VERSION 5.8 ;
BUSBITCHARS "[]" ;
DIVIDERCHAR "/" ;
UNITS
    DATABASE MICRONS 1000 ;
END UNITS

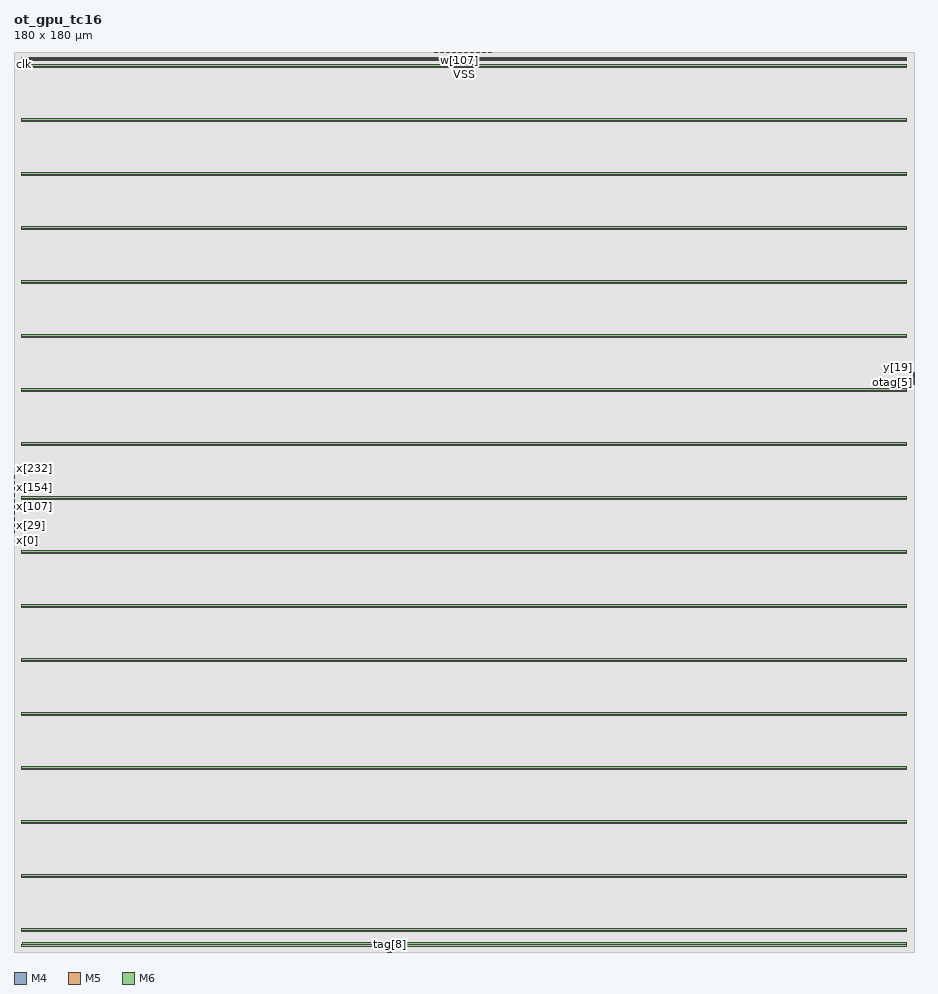
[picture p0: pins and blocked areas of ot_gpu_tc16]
MACRO ot_gpu_tc16
  FOREIGN ot_gpu_tc16 0 0 ;
  CLASS BLOCK ;
  SIZE 180 BY 180 ;
  PIN clk
    DIRECTION INPUT ;
    USE SIGNAL ;
    PORT
      LAYER M4 ;
        RECT  0 177.456 0.084 177.48 ;
    END
  END clk
  PIN fault
    DIRECTION OUTPUT ;
    USE SIGNAL ;
    PORT
      LAYER M4 ;
        RECT  179.916 113.52 180 113.544 ;
    END
  END fault
  PIN first
    DIRECTION INPUT ;
    USE SIGNAL ;
    PORT
      LAYER M5 ;
        RECT  74.64 0 74.664 0.084 ;
    END
  END first
  PIN last
    DIRECTION INPUT ;
    USE SIGNAL ;
    PORT
      LAYER M5 ;
        RECT  74.688 0 74.712 0.084 ;
    END
  END last
  PIN otag[0]
    DIRECTION OUTPUT ;
    USE SIGNAL ;
    PORT
      LAYER M4 ;
        RECT  179.916 113.568 180 113.592 ;
    END
  END otag[0]
  PIN otag[10]
    DIRECTION OUTPUT ;
    USE SIGNAL ;
    PORT
      LAYER M4 ;
        RECT  179.916 114.048 180 114.072 ;
    END
  END otag[10]
  PIN otag[11]
    DIRECTION OUTPUT ;
    USE SIGNAL ;
    PORT
      LAYER M4 ;
        RECT  179.916 114.096 180 114.12 ;
    END
  END otag[11]
  PIN otag[12]
    DIRECTION OUTPUT ;
    USE SIGNAL ;
    PORT
      LAYER M4 ;
        RECT  179.916 114.144 180 114.168 ;
    END
  END otag[12]
  PIN otag[13]
    DIRECTION OUTPUT ;
    USE SIGNAL ;
    PORT
      LAYER M4 ;
        RECT  179.916 114.192 180 114.216 ;
    END
  END otag[13]
  PIN otag[14]
    DIRECTION OUTPUT ;
    USE SIGNAL ;
    PORT
      LAYER M4 ;
        RECT  179.916 114.24 180 114.264 ;
    END
  END otag[14]
  PIN otag[15]
    DIRECTION OUTPUT ;
    USE SIGNAL ;
    PORT
      LAYER M4 ;
        RECT  179.916 114.288 180 114.312 ;
    END
  END otag[15]
  PIN otag[1]
    DIRECTION OUTPUT ;
    USE SIGNAL ;
    PORT
      LAYER M4 ;
        RECT  179.916 113.616 180 113.64 ;
    END
  END otag[1]
  PIN otag[2]
    DIRECTION OUTPUT ;
    USE SIGNAL ;
    PORT
      LAYER M4 ;
        RECT  179.916 113.664 180 113.688 ;
    END
  END otag[2]
  PIN otag[3]
    DIRECTION OUTPUT ;
    USE SIGNAL ;
    PORT
      LAYER M4 ;
        RECT  179.916 113.712 180 113.736 ;
    END
  END otag[3]
  PIN otag[4]
    DIRECTION OUTPUT ;
    USE SIGNAL ;
    PORT
      LAYER M4 ;
        RECT  179.916 113.76 180 113.784 ;
    END
  END otag[4]
  PIN otag[5]
    DIRECTION OUTPUT ;
    USE SIGNAL ;
    PORT
      LAYER M4 ;
        RECT  179.916 113.808 180 113.832 ;
    END
  END otag[5]
  PIN otag[6]
    DIRECTION OUTPUT ;
    USE SIGNAL ;
    PORT
      LAYER M4 ;
        RECT  179.916 113.856 180 113.88 ;
    END
  END otag[6]
  PIN otag[7]
    DIRECTION OUTPUT ;
    USE SIGNAL ;
    PORT
      LAYER M4 ;
        RECT  179.916 113.904 180 113.928 ;
    END
  END otag[7]
  PIN otag[8]
    DIRECTION OUTPUT ;
    USE SIGNAL ;
    PORT
      LAYER M4 ;
        RECT  179.916 113.952 180 113.976 ;
    END
  END otag[8]
  PIN otag[9]
    DIRECTION OUTPUT ;
    USE SIGNAL ;
    PORT
      LAYER M4 ;
        RECT  179.916 114 180 114.024 ;
    END
  END otag[9]
  PIN ov
    DIRECTION OUTPUT ;
    USE SIGNAL ;
    PORT
      LAYER M4 ;
        RECT  179.916 114.336 180 114.36 ;
    END
  END ov
  PIN rst_n
    DIRECTION INPUT ;
    USE SIGNAL ;
    PORT
      LAYER M5 ;
        RECT  74.736 0 74.76 0.084 ;
    END
  END rst_n
  PIN tag[0]
    DIRECTION INPUT ;
    USE SIGNAL ;
    PORT
      LAYER M5 ;
        RECT  74.784 0 74.808 0.084 ;
    END
  END tag[0]
  PIN tag[10]
    DIRECTION INPUT ;
    USE SIGNAL ;
    PORT
      LAYER M5 ;
        RECT  75.264 0 75.288 0.084 ;
    END
  END tag[10]
  PIN tag[11]
    DIRECTION INPUT ;
    USE SIGNAL ;
    PORT
      LAYER M5 ;
        RECT  75.312 0 75.336 0.084 ;
    END
  END tag[11]
  PIN tag[12]
    DIRECTION INPUT ;
    USE SIGNAL ;
    PORT
      LAYER M5 ;
        RECT  75.36 0 75.384 0.084 ;
    END
  END tag[12]
  PIN tag[13]
    DIRECTION INPUT ;
    USE SIGNAL ;
    PORT
      LAYER M5 ;
        RECT  75.408 0 75.432 0.084 ;
    END
  END tag[13]
  PIN tag[14]
    DIRECTION INPUT ;
    USE SIGNAL ;
    PORT
      LAYER M5 ;
        RECT  75.456 0 75.48 0.084 ;
    END
  END tag[14]
  PIN tag[15]
    DIRECTION INPUT ;
    USE SIGNAL ;
    PORT
      LAYER M5 ;
        RECT  75.504 0 75.528 0.084 ;
    END
  END tag[15]
  PIN tag[1]
    DIRECTION INPUT ;
    USE SIGNAL ;
    PORT
      LAYER M5 ;
        RECT  74.832 0 74.856 0.084 ;
    END
  END tag[1]
  PIN tag[2]
    DIRECTION INPUT ;
    USE SIGNAL ;
    PORT
      LAYER M5 ;
        RECT  74.88 0 74.904 0.084 ;
    END
  END tag[2]
  PIN tag[3]
    DIRECTION INPUT ;
    USE SIGNAL ;
    PORT
      LAYER M5 ;
        RECT  74.928 0 74.952 0.084 ;
    END
  END tag[3]
  PIN tag[4]
    DIRECTION INPUT ;
    USE SIGNAL ;
    PORT
      LAYER M5 ;
        RECT  74.976 0 75 0.084 ;
    END
  END tag[4]
  PIN tag[5]
    DIRECTION INPUT ;
    USE SIGNAL ;
    PORT
      LAYER M5 ;
        RECT  75.024 0 75.048 0.084 ;
    END
  END tag[5]
  PIN tag[6]
    DIRECTION INPUT ;
    USE SIGNAL ;
    PORT
      LAYER M5 ;
        RECT  75.072 0 75.096 0.084 ;
    END
  END tag[6]
  PIN tag[7]
    DIRECTION INPUT ;
    USE SIGNAL ;
    PORT
      LAYER M5 ;
        RECT  75.12 0 75.144 0.084 ;
    END
  END tag[7]
  PIN tag[8]
    DIRECTION INPUT ;
    USE SIGNAL ;
    PORT
      LAYER M5 ;
        RECT  75.168 0 75.192 0.084 ;
    END
  END tag[8]
  PIN tag[9]
    DIRECTION INPUT ;
    USE SIGNAL ;
    PORT
      LAYER M5 ;
        RECT  75.216 0 75.24 0.084 ;
    END
  END tag[9]
  PIN v
    DIRECTION INPUT ;
    USE SIGNAL ;
    PORT
      LAYER M5 ;
        RECT  75.552 0 75.576 0.084 ;
    END
  END v
  PIN w[0]
    DIRECTION INPUT ;
    USE SIGNAL ;
    PORT
      LAYER M5 ;
        RECT  83.904 179.916 83.928 180 ;
    END
  END w[0]
  PIN w[100]
    DIRECTION INPUT ;
    USE SIGNAL ;
    PORT
      LAYER M5 ;
        RECT  88.704 179.916 88.728 180 ;
    END
  END w[100]
  PIN w[101]
    DIRECTION INPUT ;
    USE SIGNAL ;
    PORT
      LAYER M5 ;
        RECT  88.752 179.916 88.776 180 ;
    END
  END w[101]
  PIN w[102]
    DIRECTION INPUT ;
    USE SIGNAL ;
    PORT
      LAYER M5 ;
        RECT  88.8 179.916 88.824 180 ;
    END
  END w[102]
  PIN w[103]
    DIRECTION INPUT ;
    USE SIGNAL ;
    PORT
      LAYER M5 ;
        RECT  88.848 179.916 88.872 180 ;
    END
  END w[103]
  PIN w[104]
    DIRECTION INPUT ;
    USE SIGNAL ;
    PORT
      LAYER M5 ;
        RECT  88.896 179.916 88.92 180 ;
    END
  END w[104]
  PIN w[105]
    DIRECTION INPUT ;
    USE SIGNAL ;
    PORT
      LAYER M5 ;
        RECT  88.944 179.916 88.968 180 ;
    END
  END w[105]
  PIN w[106]
    DIRECTION INPUT ;
    USE SIGNAL ;
    PORT
      LAYER M5 ;
        RECT  88.992 179.916 89.016 180 ;
    END
  END w[106]
  PIN w[107]
    DIRECTION INPUT ;
    USE SIGNAL ;
    PORT
      LAYER M5 ;
        RECT  89.04 179.916 89.064 180 ;
    END
  END w[107]
  PIN w[108]
    DIRECTION INPUT ;
    USE SIGNAL ;
    PORT
      LAYER M5 ;
        RECT  89.088 179.916 89.112 180 ;
    END
  END w[108]
  PIN w[109]
    DIRECTION INPUT ;
    USE SIGNAL ;
    PORT
      LAYER M5 ;
        RECT  89.136 179.916 89.16 180 ;
    END
  END w[109]
  PIN w[10]
    DIRECTION INPUT ;
    USE SIGNAL ;
    PORT
      LAYER M5 ;
        RECT  84.384 179.916 84.408 180 ;
    END
  END w[10]
  PIN w[110]
    DIRECTION INPUT ;
    USE SIGNAL ;
    PORT
      LAYER M5 ;
        RECT  89.184 179.916 89.208 180 ;
    END
  END w[110]
  PIN w[111]
    DIRECTION INPUT ;
    USE SIGNAL ;
    PORT
      LAYER M5 ;
        RECT  89.232 179.916 89.256 180 ;
    END
  END w[111]
  PIN w[112]
    DIRECTION INPUT ;
    USE SIGNAL ;
    PORT
      LAYER M5 ;
        RECT  89.28 179.916 89.304 180 ;
    END
  END w[112]
  PIN w[113]
    DIRECTION INPUT ;
    USE SIGNAL ;
    PORT
      LAYER M5 ;
        RECT  89.328 179.916 89.352 180 ;
    END
  END w[113]
  PIN w[114]
    DIRECTION INPUT ;
    USE SIGNAL ;
    PORT
      LAYER M5 ;
        RECT  89.376 179.916 89.4 180 ;
    END
  END w[114]
  PIN w[115]
    DIRECTION INPUT ;
    USE SIGNAL ;
    PORT
      LAYER M5 ;
        RECT  89.424 179.916 89.448 180 ;
    END
  END w[115]
  PIN w[116]
    DIRECTION INPUT ;
    USE SIGNAL ;
    PORT
      LAYER M5 ;
        RECT  89.472 179.916 89.496 180 ;
    END
  END w[116]
  PIN w[117]
    DIRECTION INPUT ;
    USE SIGNAL ;
    PORT
      LAYER M5 ;
        RECT  89.52 179.916 89.544 180 ;
    END
  END w[117]
  PIN w[118]
    DIRECTION INPUT ;
    USE SIGNAL ;
    PORT
      LAYER M5 ;
        RECT  89.568 179.916 89.592 180 ;
    END
  END w[118]
  PIN w[119]
    DIRECTION INPUT ;
    USE SIGNAL ;
    PORT
      LAYER M5 ;
        RECT  89.616 179.916 89.64 180 ;
    END
  END w[119]
  PIN w[11]
    DIRECTION INPUT ;
    USE SIGNAL ;
    PORT
      LAYER M5 ;
        RECT  84.432 179.916 84.456 180 ;
    END
  END w[11]
  PIN w[120]
    DIRECTION INPUT ;
    USE SIGNAL ;
    PORT
      LAYER M5 ;
        RECT  89.664 179.916 89.688 180 ;
    END
  END w[120]
  PIN w[121]
    DIRECTION INPUT ;
    USE SIGNAL ;
    PORT
      LAYER M5 ;
        RECT  89.712 179.916 89.736 180 ;
    END
  END w[121]
  PIN w[122]
    DIRECTION INPUT ;
    USE SIGNAL ;
    PORT
      LAYER M5 ;
        RECT  89.76 179.916 89.784 180 ;
    END
  END w[122]
  PIN w[123]
    DIRECTION INPUT ;
    USE SIGNAL ;
    PORT
      LAYER M5 ;
        RECT  89.808 179.916 89.832 180 ;
    END
  END w[123]
  PIN w[124]
    DIRECTION INPUT ;
    USE SIGNAL ;
    PORT
      LAYER M5 ;
        RECT  89.856 179.916 89.88 180 ;
    END
  END w[124]
  PIN w[125]
    DIRECTION INPUT ;
    USE SIGNAL ;
    PORT
      LAYER M5 ;
        RECT  89.904 179.916 89.928 180 ;
    END
  END w[125]
  PIN w[126]
    DIRECTION INPUT ;
    USE SIGNAL ;
    PORT
      LAYER M5 ;
        RECT  89.952 179.916 89.976 180 ;
    END
  END w[126]
  PIN w[127]
    DIRECTION INPUT ;
    USE SIGNAL ;
    PORT
      LAYER M5 ;
        RECT  90 179.916 90.024 180 ;
    END
  END w[127]
  PIN w[128]
    DIRECTION INPUT ;
    USE SIGNAL ;
    PORT
      LAYER M5 ;
        RECT  90.048 179.916 90.072 180 ;
    END
  END w[128]
  PIN w[129]
    DIRECTION INPUT ;
    USE SIGNAL ;
    PORT
      LAYER M5 ;
        RECT  90.096 179.916 90.12 180 ;
    END
  END w[129]
  PIN w[12]
    DIRECTION INPUT ;
    USE SIGNAL ;
    PORT
      LAYER M5 ;
        RECT  84.48 179.916 84.504 180 ;
    END
  END w[12]
  PIN w[130]
    DIRECTION INPUT ;
    USE SIGNAL ;
    PORT
      LAYER M5 ;
        RECT  90.144 179.916 90.168 180 ;
    END
  END w[130]
  PIN w[131]
    DIRECTION INPUT ;
    USE SIGNAL ;
    PORT
      LAYER M5 ;
        RECT  90.192 179.916 90.216 180 ;
    END
  END w[131]
  PIN w[132]
    DIRECTION INPUT ;
    USE SIGNAL ;
    PORT
      LAYER M5 ;
        RECT  90.24 179.916 90.264 180 ;
    END
  END w[132]
  PIN w[133]
    DIRECTION INPUT ;
    USE SIGNAL ;
    PORT
      LAYER M5 ;
        RECT  90.288 179.916 90.312 180 ;
    END
  END w[133]
  PIN w[134]
    DIRECTION INPUT ;
    USE SIGNAL ;
    PORT
      LAYER M5 ;
        RECT  90.336 179.916 90.36 180 ;
    END
  END w[134]
  PIN w[135]
    DIRECTION INPUT ;
    USE SIGNAL ;
    PORT
      LAYER M5 ;
        RECT  90.384 179.916 90.408 180 ;
    END
  END w[135]
  PIN w[136]
    DIRECTION INPUT ;
    USE SIGNAL ;
    PORT
      LAYER M5 ;
        RECT  90.432 179.916 90.456 180 ;
    END
  END w[136]
  PIN w[137]
    DIRECTION INPUT ;
    USE SIGNAL ;
    PORT
      LAYER M5 ;
        RECT  90.48 179.916 90.504 180 ;
    END
  END w[137]
  PIN w[138]
    DIRECTION INPUT ;
    USE SIGNAL ;
    PORT
      LAYER M5 ;
        RECT  90.528 179.916 90.552 180 ;
    END
  END w[138]
  PIN w[139]
    DIRECTION INPUT ;
    USE SIGNAL ;
    PORT
      LAYER M5 ;
        RECT  90.576 179.916 90.6 180 ;
    END
  END w[139]
  PIN w[13]
    DIRECTION INPUT ;
    USE SIGNAL ;
    PORT
      LAYER M5 ;
        RECT  84.528 179.916 84.552 180 ;
    END
  END w[13]
  PIN w[140]
    DIRECTION INPUT ;
    USE SIGNAL ;
    PORT
      LAYER M5 ;
        RECT  90.624 179.916 90.648 180 ;
    END
  END w[140]
  PIN w[141]
    DIRECTION INPUT ;
    USE SIGNAL ;
    PORT
      LAYER M5 ;
        RECT  90.672 179.916 90.696 180 ;
    END
  END w[141]
  PIN w[142]
    DIRECTION INPUT ;
    USE SIGNAL ;
    PORT
      LAYER M5 ;
        RECT  90.72 179.916 90.744 180 ;
    END
  END w[142]
  PIN w[143]
    DIRECTION INPUT ;
    USE SIGNAL ;
    PORT
      LAYER M5 ;
        RECT  90.768 179.916 90.792 180 ;
    END
  END w[143]
  PIN w[144]
    DIRECTION INPUT ;
    USE SIGNAL ;
    PORT
      LAYER M5 ;
        RECT  90.816 179.916 90.84 180 ;
    END
  END w[144]
  PIN w[145]
    DIRECTION INPUT ;
    USE SIGNAL ;
    PORT
      LAYER M5 ;
        RECT  90.864 179.916 90.888 180 ;
    END
  END w[145]
  PIN w[146]
    DIRECTION INPUT ;
    USE SIGNAL ;
    PORT
      LAYER M5 ;
        RECT  90.912 179.916 90.936 180 ;
    END
  END w[146]
  PIN w[147]
    DIRECTION INPUT ;
    USE SIGNAL ;
    PORT
      LAYER M5 ;
        RECT  90.96 179.916 90.984 180 ;
    END
  END w[147]
  PIN w[148]
    DIRECTION INPUT ;
    USE SIGNAL ;
    PORT
      LAYER M5 ;
        RECT  91.008 179.916 91.032 180 ;
    END
  END w[148]
  PIN w[149]
    DIRECTION INPUT ;
    USE SIGNAL ;
    PORT
      LAYER M5 ;
        RECT  91.056 179.916 91.08 180 ;
    END
  END w[149]
  PIN w[14]
    DIRECTION INPUT ;
    USE SIGNAL ;
    PORT
      LAYER M5 ;
        RECT  84.576 179.916 84.6 180 ;
    END
  END w[14]
  PIN w[150]
    DIRECTION INPUT ;
    USE SIGNAL ;
    PORT
      LAYER M5 ;
        RECT  91.104 179.916 91.128 180 ;
    END
  END w[150]
  PIN w[151]
    DIRECTION INPUT ;
    USE SIGNAL ;
    PORT
      LAYER M5 ;
        RECT  91.152 179.916 91.176 180 ;
    END
  END w[151]
  PIN w[152]
    DIRECTION INPUT ;
    USE SIGNAL ;
    PORT
      LAYER M5 ;
        RECT  91.2 179.916 91.224 180 ;
    END
  END w[152]
  PIN w[153]
    DIRECTION INPUT ;
    USE SIGNAL ;
    PORT
      LAYER M5 ;
        RECT  91.248 179.916 91.272 180 ;
    END
  END w[153]
  PIN w[154]
    DIRECTION INPUT ;
    USE SIGNAL ;
    PORT
      LAYER M5 ;
        RECT  91.296 179.916 91.32 180 ;
    END
  END w[154]
  PIN w[155]
    DIRECTION INPUT ;
    USE SIGNAL ;
    PORT
      LAYER M5 ;
        RECT  91.344 179.916 91.368 180 ;
    END
  END w[155]
  PIN w[156]
    DIRECTION INPUT ;
    USE SIGNAL ;
    PORT
      LAYER M5 ;
        RECT  91.392 179.916 91.416 180 ;
    END
  END w[156]
  PIN w[157]
    DIRECTION INPUT ;
    USE SIGNAL ;
    PORT
      LAYER M5 ;
        RECT  91.44 179.916 91.464 180 ;
    END
  END w[157]
  PIN w[158]
    DIRECTION INPUT ;
    USE SIGNAL ;
    PORT
      LAYER M5 ;
        RECT  91.488 179.916 91.512 180 ;
    END
  END w[158]
  PIN w[159]
    DIRECTION INPUT ;
    USE SIGNAL ;
    PORT
      LAYER M5 ;
        RECT  91.536 179.916 91.56 180 ;
    END
  END w[159]
  PIN w[15]
    DIRECTION INPUT ;
    USE SIGNAL ;
    PORT
      LAYER M5 ;
        RECT  84.624 179.916 84.648 180 ;
    END
  END w[15]
  PIN w[160]
    DIRECTION INPUT ;
    USE SIGNAL ;
    PORT
      LAYER M5 ;
        RECT  91.584 179.916 91.608 180 ;
    END
  END w[160]
  PIN w[161]
    DIRECTION INPUT ;
    USE SIGNAL ;
    PORT
      LAYER M5 ;
        RECT  91.632 179.916 91.656 180 ;
    END
  END w[161]
  PIN w[162]
    DIRECTION INPUT ;
    USE SIGNAL ;
    PORT
      LAYER M5 ;
        RECT  91.68 179.916 91.704 180 ;
    END
  END w[162]
  PIN w[163]
    DIRECTION INPUT ;
    USE SIGNAL ;
    PORT
      LAYER M5 ;
        RECT  91.728 179.916 91.752 180 ;
    END
  END w[163]
  PIN w[164]
    DIRECTION INPUT ;
    USE SIGNAL ;
    PORT
      LAYER M5 ;
        RECT  91.776 179.916 91.8 180 ;
    END
  END w[164]
  PIN w[165]
    DIRECTION INPUT ;
    USE SIGNAL ;
    PORT
      LAYER M5 ;
        RECT  91.824 179.916 91.848 180 ;
    END
  END w[165]
  PIN w[166]
    DIRECTION INPUT ;
    USE SIGNAL ;
    PORT
      LAYER M5 ;
        RECT  91.872 179.916 91.896 180 ;
    END
  END w[166]
  PIN w[167]
    DIRECTION INPUT ;
    USE SIGNAL ;
    PORT
      LAYER M5 ;
        RECT  91.92 179.916 91.944 180 ;
    END
  END w[167]
  PIN w[168]
    DIRECTION INPUT ;
    USE SIGNAL ;
    PORT
      LAYER M5 ;
        RECT  91.968 179.916 91.992 180 ;
    END
  END w[168]
  PIN w[169]
    DIRECTION INPUT ;
    USE SIGNAL ;
    PORT
      LAYER M5 ;
        RECT  92.016 179.916 92.04 180 ;
    END
  END w[169]
  PIN w[16]
    DIRECTION INPUT ;
    USE SIGNAL ;
    PORT
      LAYER M5 ;
        RECT  84.672 179.916 84.696 180 ;
    END
  END w[16]
  PIN w[170]
    DIRECTION INPUT ;
    USE SIGNAL ;
    PORT
      LAYER M5 ;
        RECT  92.064 179.916 92.088 180 ;
    END
  END w[170]
  PIN w[171]
    DIRECTION INPUT ;
    USE SIGNAL ;
    PORT
      LAYER M5 ;
        RECT  92.112 179.916 92.136 180 ;
    END
  END w[171]
  PIN w[172]
    DIRECTION INPUT ;
    USE SIGNAL ;
    PORT
      LAYER M5 ;
        RECT  92.16 179.916 92.184 180 ;
    END
  END w[172]
  PIN w[173]
    DIRECTION INPUT ;
    USE SIGNAL ;
    PORT
      LAYER M5 ;
        RECT  92.208 179.916 92.232 180 ;
    END
  END w[173]
  PIN w[174]
    DIRECTION INPUT ;
    USE SIGNAL ;
    PORT
      LAYER M5 ;
        RECT  92.256 179.916 92.28 180 ;
    END
  END w[174]
  PIN w[175]
    DIRECTION INPUT ;
    USE SIGNAL ;
    PORT
      LAYER M5 ;
        RECT  92.304 179.916 92.328 180 ;
    END
  END w[175]
  PIN w[176]
    DIRECTION INPUT ;
    USE SIGNAL ;
    PORT
      LAYER M5 ;
        RECT  92.352 179.916 92.376 180 ;
    END
  END w[176]
  PIN w[177]
    DIRECTION INPUT ;
    USE SIGNAL ;
    PORT
      LAYER M5 ;
        RECT  92.4 179.916 92.424 180 ;
    END
  END w[177]
  PIN w[178]
    DIRECTION INPUT ;
    USE SIGNAL ;
    PORT
      LAYER M5 ;
        RECT  92.448 179.916 92.472 180 ;
    END
  END w[178]
  PIN w[179]
    DIRECTION INPUT ;
    USE SIGNAL ;
    PORT
      LAYER M5 ;
        RECT  92.496 179.916 92.52 180 ;
    END
  END w[179]
  PIN w[17]
    DIRECTION INPUT ;
    USE SIGNAL ;
    PORT
      LAYER M5 ;
        RECT  84.72 179.916 84.744 180 ;
    END
  END w[17]
  PIN w[180]
    DIRECTION INPUT ;
    USE SIGNAL ;
    PORT
      LAYER M5 ;
        RECT  92.544 179.916 92.568 180 ;
    END
  END w[180]
  PIN w[181]
    DIRECTION INPUT ;
    USE SIGNAL ;
    PORT
      LAYER M5 ;
        RECT  92.592 179.916 92.616 180 ;
    END
  END w[181]
  PIN w[182]
    DIRECTION INPUT ;
    USE SIGNAL ;
    PORT
      LAYER M5 ;
        RECT  92.64 179.916 92.664 180 ;
    END
  END w[182]
  PIN w[183]
    DIRECTION INPUT ;
    USE SIGNAL ;
    PORT
      LAYER M5 ;
        RECT  92.688 179.916 92.712 180 ;
    END
  END w[183]
  PIN w[184]
    DIRECTION INPUT ;
    USE SIGNAL ;
    PORT
      LAYER M5 ;
        RECT  92.736 179.916 92.76 180 ;
    END
  END w[184]
  PIN w[185]
    DIRECTION INPUT ;
    USE SIGNAL ;
    PORT
      LAYER M5 ;
        RECT  92.784 179.916 92.808 180 ;
    END
  END w[185]
  PIN w[186]
    DIRECTION INPUT ;
    USE SIGNAL ;
    PORT
      LAYER M5 ;
        RECT  92.832 179.916 92.856 180 ;
    END
  END w[186]
  PIN w[187]
    DIRECTION INPUT ;
    USE SIGNAL ;
    PORT
      LAYER M5 ;
        RECT  92.88 179.916 92.904 180 ;
    END
  END w[187]
  PIN w[188]
    DIRECTION INPUT ;
    USE SIGNAL ;
    PORT
      LAYER M5 ;
        RECT  92.928 179.916 92.952 180 ;
    END
  END w[188]
  PIN w[189]
    DIRECTION INPUT ;
    USE SIGNAL ;
    PORT
      LAYER M5 ;
        RECT  92.976 179.916 93 180 ;
    END
  END w[189]
  PIN w[18]
    DIRECTION INPUT ;
    USE SIGNAL ;
    PORT
      LAYER M5 ;
        RECT  84.768 179.916 84.792 180 ;
    END
  END w[18]
  PIN w[190]
    DIRECTION INPUT ;
    USE SIGNAL ;
    PORT
      LAYER M5 ;
        RECT  93.024 179.916 93.048 180 ;
    END
  END w[190]
  PIN w[191]
    DIRECTION INPUT ;
    USE SIGNAL ;
    PORT
      LAYER M5 ;
        RECT  93.072 179.916 93.096 180 ;
    END
  END w[191]
  PIN w[192]
    DIRECTION INPUT ;
    USE SIGNAL ;
    PORT
      LAYER M5 ;
        RECT  93.12 179.916 93.144 180 ;
    END
  END w[192]
  PIN w[193]
    DIRECTION INPUT ;
    USE SIGNAL ;
    PORT
      LAYER M5 ;
        RECT  93.168 179.916 93.192 180 ;
    END
  END w[193]
  PIN w[194]
    DIRECTION INPUT ;
    USE SIGNAL ;
    PORT
      LAYER M5 ;
        RECT  93.216 179.916 93.24 180 ;
    END
  END w[194]
  PIN w[195]
    DIRECTION INPUT ;
    USE SIGNAL ;
    PORT
      LAYER M5 ;
        RECT  93.264 179.916 93.288 180 ;
    END
  END w[195]
  PIN w[196]
    DIRECTION INPUT ;
    USE SIGNAL ;
    PORT
      LAYER M5 ;
        RECT  93.312 179.916 93.336 180 ;
    END
  END w[196]
  PIN w[197]
    DIRECTION INPUT ;
    USE SIGNAL ;
    PORT
      LAYER M5 ;
        RECT  93.36 179.916 93.384 180 ;
    END
  END w[197]
  PIN w[198]
    DIRECTION INPUT ;
    USE SIGNAL ;
    PORT
      LAYER M5 ;
        RECT  93.408 179.916 93.432 180 ;
    END
  END w[198]
  PIN w[199]
    DIRECTION INPUT ;
    USE SIGNAL ;
    PORT
      LAYER M5 ;
        RECT  93.456 179.916 93.48 180 ;
    END
  END w[199]
  PIN w[19]
    DIRECTION INPUT ;
    USE SIGNAL ;
    PORT
      LAYER M5 ;
        RECT  84.816 179.916 84.84 180 ;
    END
  END w[19]
  PIN w[1]
    DIRECTION INPUT ;
    USE SIGNAL ;
    PORT
      LAYER M5 ;
        RECT  83.952 179.916 83.976 180 ;
    END
  END w[1]
  PIN w[200]
    DIRECTION INPUT ;
    USE SIGNAL ;
    PORT
      LAYER M5 ;
        RECT  93.504 179.916 93.528 180 ;
    END
  END w[200]
  PIN w[201]
    DIRECTION INPUT ;
    USE SIGNAL ;
    PORT
      LAYER M5 ;
        RECT  93.552 179.916 93.576 180 ;
    END
  END w[201]
  PIN w[202]
    DIRECTION INPUT ;
    USE SIGNAL ;
    PORT
      LAYER M5 ;
        RECT  93.6 179.916 93.624 180 ;
    END
  END w[202]
  PIN w[203]
    DIRECTION INPUT ;
    USE SIGNAL ;
    PORT
      LAYER M5 ;
        RECT  93.648 179.916 93.672 180 ;
    END
  END w[203]
  PIN w[204]
    DIRECTION INPUT ;
    USE SIGNAL ;
    PORT
      LAYER M5 ;
        RECT  93.696 179.916 93.72 180 ;
    END
  END w[204]
  PIN w[205]
    DIRECTION INPUT ;
    USE SIGNAL ;
    PORT
      LAYER M5 ;
        RECT  93.744 179.916 93.768 180 ;
    END
  END w[205]
  PIN w[206]
    DIRECTION INPUT ;
    USE SIGNAL ;
    PORT
      LAYER M5 ;
        RECT  93.792 179.916 93.816 180 ;
    END
  END w[206]
  PIN w[207]
    DIRECTION INPUT ;
    USE SIGNAL ;
    PORT
      LAYER M5 ;
        RECT  93.84 179.916 93.864 180 ;
    END
  END w[207]
  PIN w[208]
    DIRECTION INPUT ;
    USE SIGNAL ;
    PORT
      LAYER M5 ;
        RECT  93.888 179.916 93.912 180 ;
    END
  END w[208]
  PIN w[209]
    DIRECTION INPUT ;
    USE SIGNAL ;
    PORT
      LAYER M5 ;
        RECT  93.936 179.916 93.96 180 ;
    END
  END w[209]
  PIN w[20]
    DIRECTION INPUT ;
    USE SIGNAL ;
    PORT
      LAYER M5 ;
        RECT  84.864 179.916 84.888 180 ;
    END
  END w[20]
  PIN w[210]
    DIRECTION INPUT ;
    USE SIGNAL ;
    PORT
      LAYER M5 ;
        RECT  93.984 179.916 94.008 180 ;
    END
  END w[210]
  PIN w[211]
    DIRECTION INPUT ;
    USE SIGNAL ;
    PORT
      LAYER M5 ;
        RECT  94.032 179.916 94.056 180 ;
    END
  END w[211]
  PIN w[212]
    DIRECTION INPUT ;
    USE SIGNAL ;
    PORT
      LAYER M5 ;
        RECT  94.08 179.916 94.104 180 ;
    END
  END w[212]
  PIN w[213]
    DIRECTION INPUT ;
    USE SIGNAL ;
    PORT
      LAYER M5 ;
        RECT  94.128 179.916 94.152 180 ;
    END
  END w[213]
  PIN w[214]
    DIRECTION INPUT ;
    USE SIGNAL ;
    PORT
      LAYER M5 ;
        RECT  94.176 179.916 94.2 180 ;
    END
  END w[214]
  PIN w[215]
    DIRECTION INPUT ;
    USE SIGNAL ;
    PORT
      LAYER M5 ;
        RECT  94.224 179.916 94.248 180 ;
    END
  END w[215]
  PIN w[216]
    DIRECTION INPUT ;
    USE SIGNAL ;
    PORT
      LAYER M5 ;
        RECT  94.272 179.916 94.296 180 ;
    END
  END w[216]
  PIN w[217]
    DIRECTION INPUT ;
    USE SIGNAL ;
    PORT
      LAYER M5 ;
        RECT  94.32 179.916 94.344 180 ;
    END
  END w[217]
  PIN w[218]
    DIRECTION INPUT ;
    USE SIGNAL ;
    PORT
      LAYER M5 ;
        RECT  94.368 179.916 94.392 180 ;
    END
  END w[218]
  PIN w[219]
    DIRECTION INPUT ;
    USE SIGNAL ;
    PORT
      LAYER M5 ;
        RECT  94.416 179.916 94.44 180 ;
    END
  END w[219]
  PIN w[21]
    DIRECTION INPUT ;
    USE SIGNAL ;
    PORT
      LAYER M5 ;
        RECT  84.912 179.916 84.936 180 ;
    END
  END w[21]
  PIN w[220]
    DIRECTION INPUT ;
    USE SIGNAL ;
    PORT
      LAYER M5 ;
        RECT  94.464 179.916 94.488 180 ;
    END
  END w[220]
  PIN w[221]
    DIRECTION INPUT ;
    USE SIGNAL ;
    PORT
      LAYER M5 ;
        RECT  94.512 179.916 94.536 180 ;
    END
  END w[221]
  PIN w[222]
    DIRECTION INPUT ;
    USE SIGNAL ;
    PORT
      LAYER M5 ;
        RECT  94.56 179.916 94.584 180 ;
    END
  END w[222]
  PIN w[223]
    DIRECTION INPUT ;
    USE SIGNAL ;
    PORT
      LAYER M5 ;
        RECT  94.608 179.916 94.632 180 ;
    END
  END w[223]
  PIN w[224]
    DIRECTION INPUT ;
    USE SIGNAL ;
    PORT
      LAYER M5 ;
        RECT  94.656 179.916 94.68 180 ;
    END
  END w[224]
  PIN w[225]
    DIRECTION INPUT ;
    USE SIGNAL ;
    PORT
      LAYER M5 ;
        RECT  94.704 179.916 94.728 180 ;
    END
  END w[225]
  PIN w[226]
    DIRECTION INPUT ;
    USE SIGNAL ;
    PORT
      LAYER M5 ;
        RECT  94.752 179.916 94.776 180 ;
    END
  END w[226]
  PIN w[227]
    DIRECTION INPUT ;
    USE SIGNAL ;
    PORT
      LAYER M5 ;
        RECT  94.8 179.916 94.824 180 ;
    END
  END w[227]
  PIN w[228]
    DIRECTION INPUT ;
    USE SIGNAL ;
    PORT
      LAYER M5 ;
        RECT  94.848 179.916 94.872 180 ;
    END
  END w[228]
  PIN w[229]
    DIRECTION INPUT ;
    USE SIGNAL ;
    PORT
      LAYER M5 ;
        RECT  94.896 179.916 94.92 180 ;
    END
  END w[229]
  PIN w[22]
    DIRECTION INPUT ;
    USE SIGNAL ;
    PORT
      LAYER M5 ;
        RECT  84.96 179.916 84.984 180 ;
    END
  END w[22]
  PIN w[230]
    DIRECTION INPUT ;
    USE SIGNAL ;
    PORT
      LAYER M5 ;
        RECT  94.944 179.916 94.968 180 ;
    END
  END w[230]
  PIN w[231]
    DIRECTION INPUT ;
    USE SIGNAL ;
    PORT
      LAYER M5 ;
        RECT  94.992 179.916 95.016 180 ;
    END
  END w[231]
  PIN w[232]
    DIRECTION INPUT ;
    USE SIGNAL ;
    PORT
      LAYER M5 ;
        RECT  95.04 179.916 95.064 180 ;
    END
  END w[232]
  PIN w[233]
    DIRECTION INPUT ;
    USE SIGNAL ;
    PORT
      LAYER M5 ;
        RECT  95.088 179.916 95.112 180 ;
    END
  END w[233]
  PIN w[234]
    DIRECTION INPUT ;
    USE SIGNAL ;
    PORT
      LAYER M5 ;
        RECT  95.136 179.916 95.16 180 ;
    END
  END w[234]
  PIN w[235]
    DIRECTION INPUT ;
    USE SIGNAL ;
    PORT
      LAYER M5 ;
        RECT  95.184 179.916 95.208 180 ;
    END
  END w[235]
  PIN w[236]
    DIRECTION INPUT ;
    USE SIGNAL ;
    PORT
      LAYER M5 ;
        RECT  95.232 179.916 95.256 180 ;
    END
  END w[236]
  PIN w[237]
    DIRECTION INPUT ;
    USE SIGNAL ;
    PORT
      LAYER M5 ;
        RECT  95.28 179.916 95.304 180 ;
    END
  END w[237]
  PIN w[238]
    DIRECTION INPUT ;
    USE SIGNAL ;
    PORT
      LAYER M5 ;
        RECT  95.328 179.916 95.352 180 ;
    END
  END w[238]
  PIN w[239]
    DIRECTION INPUT ;
    USE SIGNAL ;
    PORT
      LAYER M5 ;
        RECT  95.376 179.916 95.4 180 ;
    END
  END w[239]
  PIN w[23]
    DIRECTION INPUT ;
    USE SIGNAL ;
    PORT
      LAYER M5 ;
        RECT  85.008 179.916 85.032 180 ;
    END
  END w[23]
  PIN w[240]
    DIRECTION INPUT ;
    USE SIGNAL ;
    PORT
      LAYER M5 ;
        RECT  95.424 179.916 95.448 180 ;
    END
  END w[240]
  PIN w[241]
    DIRECTION INPUT ;
    USE SIGNAL ;
    PORT
      LAYER M5 ;
        RECT  95.472 179.916 95.496 180 ;
    END
  END w[241]
  PIN w[242]
    DIRECTION INPUT ;
    USE SIGNAL ;
    PORT
      LAYER M5 ;
        RECT  95.52 179.916 95.544 180 ;
    END
  END w[242]
  PIN w[243]
    DIRECTION INPUT ;
    USE SIGNAL ;
    PORT
      LAYER M5 ;
        RECT  95.568 179.916 95.592 180 ;
    END
  END w[243]
  PIN w[244]
    DIRECTION INPUT ;
    USE SIGNAL ;
    PORT
      LAYER M5 ;
        RECT  95.616 179.916 95.64 180 ;
    END
  END w[244]
  PIN w[245]
    DIRECTION INPUT ;
    USE SIGNAL ;
    PORT
      LAYER M5 ;
        RECT  95.664 179.916 95.688 180 ;
    END
  END w[245]
  PIN w[246]
    DIRECTION INPUT ;
    USE SIGNAL ;
    PORT
      LAYER M5 ;
        RECT  95.712 179.916 95.736 180 ;
    END
  END w[246]
  PIN w[247]
    DIRECTION INPUT ;
    USE SIGNAL ;
    PORT
      LAYER M5 ;
        RECT  95.76 179.916 95.784 180 ;
    END
  END w[247]
  PIN w[248]
    DIRECTION INPUT ;
    USE SIGNAL ;
    PORT
      LAYER M5 ;
        RECT  95.808 179.916 95.832 180 ;
    END
  END w[248]
  PIN w[249]
    DIRECTION INPUT ;
    USE SIGNAL ;
    PORT
      LAYER M5 ;
        RECT  95.856 179.916 95.88 180 ;
    END
  END w[249]
  PIN w[24]
    DIRECTION INPUT ;
    USE SIGNAL ;
    PORT
      LAYER M5 ;
        RECT  85.056 179.916 85.08 180 ;
    END
  END w[24]
  PIN w[250]
    DIRECTION INPUT ;
    USE SIGNAL ;
    PORT
      LAYER M5 ;
        RECT  95.904 179.916 95.928 180 ;
    END
  END w[250]
  PIN w[251]
    DIRECTION INPUT ;
    USE SIGNAL ;
    PORT
      LAYER M5 ;
        RECT  95.952 179.916 95.976 180 ;
    END
  END w[251]
  PIN w[252]
    DIRECTION INPUT ;
    USE SIGNAL ;
    PORT
      LAYER M5 ;
        RECT  96 179.916 96.024 180 ;
    END
  END w[252]
  PIN w[253]
    DIRECTION INPUT ;
    USE SIGNAL ;
    PORT
      LAYER M5 ;
        RECT  96.048 179.916 96.072 180 ;
    END
  END w[253]
  PIN w[254]
    DIRECTION INPUT ;
    USE SIGNAL ;
    PORT
      LAYER M5 ;
        RECT  96.096 179.916 96.12 180 ;
    END
  END w[254]
  PIN w[255]
    DIRECTION INPUT ;
    USE SIGNAL ;
    PORT
      LAYER M5 ;
        RECT  96.144 179.916 96.168 180 ;
    END
  END w[255]
  PIN w[25]
    DIRECTION INPUT ;
    USE SIGNAL ;
    PORT
      LAYER M5 ;
        RECT  85.104 179.916 85.128 180 ;
    END
  END w[25]
  PIN w[26]
    DIRECTION INPUT ;
    USE SIGNAL ;
    PORT
      LAYER M5 ;
        RECT  85.152 179.916 85.176 180 ;
    END
  END w[26]
  PIN w[27]
    DIRECTION INPUT ;
    USE SIGNAL ;
    PORT
      LAYER M5 ;
        RECT  85.2 179.916 85.224 180 ;
    END
  END w[27]
  PIN w[28]
    DIRECTION INPUT ;
    USE SIGNAL ;
    PORT
      LAYER M5 ;
        RECT  85.248 179.916 85.272 180 ;
    END
  END w[28]
  PIN w[29]
    DIRECTION INPUT ;
    USE SIGNAL ;
    PORT
      LAYER M5 ;
        RECT  85.296 179.916 85.32 180 ;
    END
  END w[29]
  PIN w[2]
    DIRECTION INPUT ;
    USE SIGNAL ;
    PORT
      LAYER M5 ;
        RECT  84 179.916 84.024 180 ;
    END
  END w[2]
  PIN w[30]
    DIRECTION INPUT ;
    USE SIGNAL ;
    PORT
      LAYER M5 ;
        RECT  85.344 179.916 85.368 180 ;
    END
  END w[30]
  PIN w[31]
    DIRECTION INPUT ;
    USE SIGNAL ;
    PORT
      LAYER M5 ;
        RECT  85.392 179.916 85.416 180 ;
    END
  END w[31]
  PIN w[32]
    DIRECTION INPUT ;
    USE SIGNAL ;
    PORT
      LAYER M5 ;
        RECT  85.44 179.916 85.464 180 ;
    END
  END w[32]
  PIN w[33]
    DIRECTION INPUT ;
    USE SIGNAL ;
    PORT
      LAYER M5 ;
        RECT  85.488 179.916 85.512 180 ;
    END
  END w[33]
  PIN w[34]
    DIRECTION INPUT ;
    USE SIGNAL ;
    PORT
      LAYER M5 ;
        RECT  85.536 179.916 85.56 180 ;
    END
  END w[34]
  PIN w[35]
    DIRECTION INPUT ;
    USE SIGNAL ;
    PORT
      LAYER M5 ;
        RECT  85.584 179.916 85.608 180 ;
    END
  END w[35]
  PIN w[36]
    DIRECTION INPUT ;
    USE SIGNAL ;
    PORT
      LAYER M5 ;
        RECT  85.632 179.916 85.656 180 ;
    END
  END w[36]
  PIN w[37]
    DIRECTION INPUT ;
    USE SIGNAL ;
    PORT
      LAYER M5 ;
        RECT  85.68 179.916 85.704 180 ;
    END
  END w[37]
  PIN w[38]
    DIRECTION INPUT ;
    USE SIGNAL ;
    PORT
      LAYER M5 ;
        RECT  85.728 179.916 85.752 180 ;
    END
  END w[38]
  PIN w[39]
    DIRECTION INPUT ;
    USE SIGNAL ;
    PORT
      LAYER M5 ;
        RECT  85.776 179.916 85.8 180 ;
    END
  END w[39]
  PIN w[3]
    DIRECTION INPUT ;
    USE SIGNAL ;
    PORT
      LAYER M5 ;
        RECT  84.048 179.916 84.072 180 ;
    END
  END w[3]
  PIN w[40]
    DIRECTION INPUT ;
    USE SIGNAL ;
    PORT
      LAYER M5 ;
        RECT  85.824 179.916 85.848 180 ;
    END
  END w[40]
  PIN w[41]
    DIRECTION INPUT ;
    USE SIGNAL ;
    PORT
      LAYER M5 ;
        RECT  85.872 179.916 85.896 180 ;
    END
  END w[41]
  PIN w[42]
    DIRECTION INPUT ;
    USE SIGNAL ;
    PORT
      LAYER M5 ;
        RECT  85.92 179.916 85.944 180 ;
    END
  END w[42]
  PIN w[43]
    DIRECTION INPUT ;
    USE SIGNAL ;
    PORT
      LAYER M5 ;
        RECT  85.968 179.916 85.992 180 ;
    END
  END w[43]
  PIN w[44]
    DIRECTION INPUT ;
    USE SIGNAL ;
    PORT
      LAYER M5 ;
        RECT  86.016 179.916 86.04 180 ;
    END
  END w[44]
  PIN w[45]
    DIRECTION INPUT ;
    USE SIGNAL ;
    PORT
      LAYER M5 ;
        RECT  86.064 179.916 86.088 180 ;
    END
  END w[45]
  PIN w[46]
    DIRECTION INPUT ;
    USE SIGNAL ;
    PORT
      LAYER M5 ;
        RECT  86.112 179.916 86.136 180 ;
    END
  END w[46]
  PIN w[47]
    DIRECTION INPUT ;
    USE SIGNAL ;
    PORT
      LAYER M5 ;
        RECT  86.16 179.916 86.184 180 ;
    END
  END w[47]
  PIN w[48]
    DIRECTION INPUT ;
    USE SIGNAL ;
    PORT
      LAYER M5 ;
        RECT  86.208 179.916 86.232 180 ;
    END
  END w[48]
  PIN w[49]
    DIRECTION INPUT ;
    USE SIGNAL ;
    PORT
      LAYER M5 ;
        RECT  86.256 179.916 86.28 180 ;
    END
  END w[49]
  PIN w[4]
    DIRECTION INPUT ;
    USE SIGNAL ;
    PORT
      LAYER M5 ;
        RECT  84.096 179.916 84.12 180 ;
    END
  END w[4]
  PIN w[50]
    DIRECTION INPUT ;
    USE SIGNAL ;
    PORT
      LAYER M5 ;
        RECT  86.304 179.916 86.328 180 ;
    END
  END w[50]
  PIN w[51]
    DIRECTION INPUT ;
    USE SIGNAL ;
    PORT
      LAYER M5 ;
        RECT  86.352 179.916 86.376 180 ;
    END
  END w[51]
  PIN w[52]
    DIRECTION INPUT ;
    USE SIGNAL ;
    PORT
      LAYER M5 ;
        RECT  86.4 179.916 86.424 180 ;
    END
  END w[52]
  PIN w[53]
    DIRECTION INPUT ;
    USE SIGNAL ;
    PORT
      LAYER M5 ;
        RECT  86.448 179.916 86.472 180 ;
    END
  END w[53]
  PIN w[54]
    DIRECTION INPUT ;
    USE SIGNAL ;
    PORT
      LAYER M5 ;
        RECT  86.496 179.916 86.52 180 ;
    END
  END w[54]
  PIN w[55]
    DIRECTION INPUT ;
    USE SIGNAL ;
    PORT
      LAYER M5 ;
        RECT  86.544 179.916 86.568 180 ;
    END
  END w[55]
  PIN w[56]
    DIRECTION INPUT ;
    USE SIGNAL ;
    PORT
      LAYER M5 ;
        RECT  86.592 179.916 86.616 180 ;
    END
  END w[56]
  PIN w[57]
    DIRECTION INPUT ;
    USE SIGNAL ;
    PORT
      LAYER M5 ;
        RECT  86.64 179.916 86.664 180 ;
    END
  END w[57]
  PIN w[58]
    DIRECTION INPUT ;
    USE SIGNAL ;
    PORT
      LAYER M5 ;
        RECT  86.688 179.916 86.712 180 ;
    END
  END w[58]
  PIN w[59]
    DIRECTION INPUT ;
    USE SIGNAL ;
    PORT
      LAYER M5 ;
        RECT  86.736 179.916 86.76 180 ;
    END
  END w[59]
  PIN w[5]
    DIRECTION INPUT ;
    USE SIGNAL ;
    PORT
      LAYER M5 ;
        RECT  84.144 179.916 84.168 180 ;
    END
  END w[5]
  PIN w[60]
    DIRECTION INPUT ;
    USE SIGNAL ;
    PORT
      LAYER M5 ;
        RECT  86.784 179.916 86.808 180 ;
    END
  END w[60]
  PIN w[61]
    DIRECTION INPUT ;
    USE SIGNAL ;
    PORT
      LAYER M5 ;
        RECT  86.832 179.916 86.856 180 ;
    END
  END w[61]
  PIN w[62]
    DIRECTION INPUT ;
    USE SIGNAL ;
    PORT
      LAYER M5 ;
        RECT  86.88 179.916 86.904 180 ;
    END
  END w[62]
  PIN w[63]
    DIRECTION INPUT ;
    USE SIGNAL ;
    PORT
      LAYER M5 ;
        RECT  86.928 179.916 86.952 180 ;
    END
  END w[63]
  PIN w[64]
    DIRECTION INPUT ;
    USE SIGNAL ;
    PORT
      LAYER M5 ;
        RECT  86.976 179.916 87 180 ;
    END
  END w[64]
  PIN w[65]
    DIRECTION INPUT ;
    USE SIGNAL ;
    PORT
      LAYER M5 ;
        RECT  87.024 179.916 87.048 180 ;
    END
  END w[65]
  PIN w[66]
    DIRECTION INPUT ;
    USE SIGNAL ;
    PORT
      LAYER M5 ;
        RECT  87.072 179.916 87.096 180 ;
    END
  END w[66]
  PIN w[67]
    DIRECTION INPUT ;
    USE SIGNAL ;
    PORT
      LAYER M5 ;
        RECT  87.12 179.916 87.144 180 ;
    END
  END w[67]
  PIN w[68]
    DIRECTION INPUT ;
    USE SIGNAL ;
    PORT
      LAYER M5 ;
        RECT  87.168 179.916 87.192 180 ;
    END
  END w[68]
  PIN w[69]
    DIRECTION INPUT ;
    USE SIGNAL ;
    PORT
      LAYER M5 ;
        RECT  87.216 179.916 87.24 180 ;
    END
  END w[69]
  PIN w[6]
    DIRECTION INPUT ;
    USE SIGNAL ;
    PORT
      LAYER M5 ;
        RECT  84.192 179.916 84.216 180 ;
    END
  END w[6]
  PIN w[70]
    DIRECTION INPUT ;
    USE SIGNAL ;
    PORT
      LAYER M5 ;
        RECT  87.264 179.916 87.288 180 ;
    END
  END w[70]
  PIN w[71]
    DIRECTION INPUT ;
    USE SIGNAL ;
    PORT
      LAYER M5 ;
        RECT  87.312 179.916 87.336 180 ;
    END
  END w[71]
  PIN w[72]
    DIRECTION INPUT ;
    USE SIGNAL ;
    PORT
      LAYER M5 ;
        RECT  87.36 179.916 87.384 180 ;
    END
  END w[72]
  PIN w[73]
    DIRECTION INPUT ;
    USE SIGNAL ;
    PORT
      LAYER M5 ;
        RECT  87.408 179.916 87.432 180 ;
    END
  END w[73]
  PIN w[74]
    DIRECTION INPUT ;
    USE SIGNAL ;
    PORT
      LAYER M5 ;
        RECT  87.456 179.916 87.48 180 ;
    END
  END w[74]
  PIN w[75]
    DIRECTION INPUT ;
    USE SIGNAL ;
    PORT
      LAYER M5 ;
        RECT  87.504 179.916 87.528 180 ;
    END
  END w[75]
  PIN w[76]
    DIRECTION INPUT ;
    USE SIGNAL ;
    PORT
      LAYER M5 ;
        RECT  87.552 179.916 87.576 180 ;
    END
  END w[76]
  PIN w[77]
    DIRECTION INPUT ;
    USE SIGNAL ;
    PORT
      LAYER M5 ;
        RECT  87.6 179.916 87.624 180 ;
    END
  END w[77]
  PIN w[78]
    DIRECTION INPUT ;
    USE SIGNAL ;
    PORT
      LAYER M5 ;
        RECT  87.648 179.916 87.672 180 ;
    END
  END w[78]
  PIN w[79]
    DIRECTION INPUT ;
    USE SIGNAL ;
    PORT
      LAYER M5 ;
        RECT  87.696 179.916 87.72 180 ;
    END
  END w[79]
  PIN w[7]
    DIRECTION INPUT ;
    USE SIGNAL ;
    PORT
      LAYER M5 ;
        RECT  84.24 179.916 84.264 180 ;
    END
  END w[7]
  PIN w[80]
    DIRECTION INPUT ;
    USE SIGNAL ;
    PORT
      LAYER M5 ;
        RECT  87.744 179.916 87.768 180 ;
    END
  END w[80]
  PIN w[81]
    DIRECTION INPUT ;
    USE SIGNAL ;
    PORT
      LAYER M5 ;
        RECT  87.792 179.916 87.816 180 ;
    END
  END w[81]
  PIN w[82]
    DIRECTION INPUT ;
    USE SIGNAL ;
    PORT
      LAYER M5 ;
        RECT  87.84 179.916 87.864 180 ;
    END
  END w[82]
  PIN w[83]
    DIRECTION INPUT ;
    USE SIGNAL ;
    PORT
      LAYER M5 ;
        RECT  87.888 179.916 87.912 180 ;
    END
  END w[83]
  PIN w[84]
    DIRECTION INPUT ;
    USE SIGNAL ;
    PORT
      LAYER M5 ;
        RECT  87.936 179.916 87.96 180 ;
    END
  END w[84]
  PIN w[85]
    DIRECTION INPUT ;
    USE SIGNAL ;
    PORT
      LAYER M5 ;
        RECT  87.984 179.916 88.008 180 ;
    END
  END w[85]
  PIN w[86]
    DIRECTION INPUT ;
    USE SIGNAL ;
    PORT
      LAYER M5 ;
        RECT  88.032 179.916 88.056 180 ;
    END
  END w[86]
  PIN w[87]
    DIRECTION INPUT ;
    USE SIGNAL ;
    PORT
      LAYER M5 ;
        RECT  88.08 179.916 88.104 180 ;
    END
  END w[87]
  PIN w[88]
    DIRECTION INPUT ;
    USE SIGNAL ;
    PORT
      LAYER M5 ;
        RECT  88.128 179.916 88.152 180 ;
    END
  END w[88]
  PIN w[89]
    DIRECTION INPUT ;
    USE SIGNAL ;
    PORT
      LAYER M5 ;
        RECT  88.176 179.916 88.2 180 ;
    END
  END w[89]
  PIN w[8]
    DIRECTION INPUT ;
    USE SIGNAL ;
    PORT
      LAYER M5 ;
        RECT  84.288 179.916 84.312 180 ;
    END
  END w[8]
  PIN w[90]
    DIRECTION INPUT ;
    USE SIGNAL ;
    PORT
      LAYER M5 ;
        RECT  88.224 179.916 88.248 180 ;
    END
  END w[90]
  PIN w[91]
    DIRECTION INPUT ;
    USE SIGNAL ;
    PORT
      LAYER M5 ;
        RECT  88.272 179.916 88.296 180 ;
    END
  END w[91]
  PIN w[92]
    DIRECTION INPUT ;
    USE SIGNAL ;
    PORT
      LAYER M5 ;
        RECT  88.32 179.916 88.344 180 ;
    END
  END w[92]
  PIN w[93]
    DIRECTION INPUT ;
    USE SIGNAL ;
    PORT
      LAYER M5 ;
        RECT  88.368 179.916 88.392 180 ;
    END
  END w[93]
  PIN w[94]
    DIRECTION INPUT ;
    USE SIGNAL ;
    PORT
      LAYER M5 ;
        RECT  88.416 179.916 88.44 180 ;
    END
  END w[94]
  PIN w[95]
    DIRECTION INPUT ;
    USE SIGNAL ;
    PORT
      LAYER M5 ;
        RECT  88.464 179.916 88.488 180 ;
    END
  END w[95]
  PIN w[96]
    DIRECTION INPUT ;
    USE SIGNAL ;
    PORT
      LAYER M5 ;
        RECT  88.512 179.916 88.536 180 ;
    END
  END w[96]
  PIN w[97]
    DIRECTION INPUT ;
    USE SIGNAL ;
    PORT
      LAYER M5 ;
        RECT  88.56 179.916 88.584 180 ;
    END
  END w[97]
  PIN w[98]
    DIRECTION INPUT ;
    USE SIGNAL ;
    PORT
      LAYER M5 ;
        RECT  88.608 179.916 88.632 180 ;
    END
  END w[98]
  PIN w[99]
    DIRECTION INPUT ;
    USE SIGNAL ;
    PORT
      LAYER M5 ;
        RECT  88.656 179.916 88.68 180 ;
    END
  END w[99]
  PIN w[9]
    DIRECTION INPUT ;
    USE SIGNAL ;
    PORT
      LAYER M5 ;
        RECT  84.336 179.916 84.36 180 ;
    END
  END w[9]
  PIN x[0]
    DIRECTION INPUT ;
    USE SIGNAL ;
    PORT
      LAYER M4 ;
        RECT  0 83.904 0.084 83.928 ;
    END
  END x[0]
  PIN x[100]
    DIRECTION INPUT ;
    USE SIGNAL ;
    PORT
      LAYER M4 ;
        RECT  0 88.704 0.084 88.728 ;
    END
  END x[100]
  PIN x[101]
    DIRECTION INPUT ;
    USE SIGNAL ;
    PORT
      LAYER M4 ;
        RECT  0 88.752 0.084 88.776 ;
    END
  END x[101]
  PIN x[102]
    DIRECTION INPUT ;
    USE SIGNAL ;
    PORT
      LAYER M4 ;
        RECT  0 88.8 0.084 88.824 ;
    END
  END x[102]
  PIN x[103]
    DIRECTION INPUT ;
    USE SIGNAL ;
    PORT
      LAYER M4 ;
        RECT  0 88.848 0.084 88.872 ;
    END
  END x[103]
  PIN x[104]
    DIRECTION INPUT ;
    USE SIGNAL ;
    PORT
      LAYER M4 ;
        RECT  0 88.896 0.084 88.92 ;
    END
  END x[104]
  PIN x[105]
    DIRECTION INPUT ;
    USE SIGNAL ;
    PORT
      LAYER M4 ;
        RECT  0 88.944 0.084 88.968 ;
    END
  END x[105]
  PIN x[106]
    DIRECTION INPUT ;
    USE SIGNAL ;
    PORT
      LAYER M4 ;
        RECT  0 88.992 0.084 89.016 ;
    END
  END x[106]
  PIN x[107]
    DIRECTION INPUT ;
    USE SIGNAL ;
    PORT
      LAYER M4 ;
        RECT  0 89.04 0.084 89.064 ;
    END
  END x[107]
  PIN x[108]
    DIRECTION INPUT ;
    USE SIGNAL ;
    PORT
      LAYER M4 ;
        RECT  0 89.088 0.084 89.112 ;
    END
  END x[108]
  PIN x[109]
    DIRECTION INPUT ;
    USE SIGNAL ;
    PORT
      LAYER M4 ;
        RECT  0 89.136 0.084 89.16 ;
    END
  END x[109]
  PIN x[10]
    DIRECTION INPUT ;
    USE SIGNAL ;
    PORT
      LAYER M4 ;
        RECT  0 84.384 0.084 84.408 ;
    END
  END x[10]
  PIN x[110]
    DIRECTION INPUT ;
    USE SIGNAL ;
    PORT
      LAYER M4 ;
        RECT  0 89.184 0.084 89.208 ;
    END
  END x[110]
  PIN x[111]
    DIRECTION INPUT ;
    USE SIGNAL ;
    PORT
      LAYER M4 ;
        RECT  0 89.232 0.084 89.256 ;
    END
  END x[111]
  PIN x[112]
    DIRECTION INPUT ;
    USE SIGNAL ;
    PORT
      LAYER M4 ;
        RECT  0 89.28 0.084 89.304 ;
    END
  END x[112]
  PIN x[113]
    DIRECTION INPUT ;
    USE SIGNAL ;
    PORT
      LAYER M4 ;
        RECT  0 89.328 0.084 89.352 ;
    END
  END x[113]
  PIN x[114]
    DIRECTION INPUT ;
    USE SIGNAL ;
    PORT
      LAYER M4 ;
        RECT  0 89.376 0.084 89.4 ;
    END
  END x[114]
  PIN x[115]
    DIRECTION INPUT ;
    USE SIGNAL ;
    PORT
      LAYER M4 ;
        RECT  0 89.424 0.084 89.448 ;
    END
  END x[115]
  PIN x[116]
    DIRECTION INPUT ;
    USE SIGNAL ;
    PORT
      LAYER M4 ;
        RECT  0 89.472 0.084 89.496 ;
    END
  END x[116]
  PIN x[117]
    DIRECTION INPUT ;
    USE SIGNAL ;
    PORT
      LAYER M4 ;
        RECT  0 89.52 0.084 89.544 ;
    END
  END x[117]
  PIN x[118]
    DIRECTION INPUT ;
    USE SIGNAL ;
    PORT
      LAYER M4 ;
        RECT  0 89.568 0.084 89.592 ;
    END
  END x[118]
  PIN x[119]
    DIRECTION INPUT ;
    USE SIGNAL ;
    PORT
      LAYER M4 ;
        RECT  0 89.616 0.084 89.64 ;
    END
  END x[119]
  PIN x[11]
    DIRECTION INPUT ;
    USE SIGNAL ;
    PORT
      LAYER M4 ;
        RECT  0 84.432 0.084 84.456 ;
    END
  END x[11]
  PIN x[120]
    DIRECTION INPUT ;
    USE SIGNAL ;
    PORT
      LAYER M4 ;
        RECT  0 89.664 0.084 89.688 ;
    END
  END x[120]
  PIN x[121]
    DIRECTION INPUT ;
    USE SIGNAL ;
    PORT
      LAYER M4 ;
        RECT  0 89.712 0.084 89.736 ;
    END
  END x[121]
  PIN x[122]
    DIRECTION INPUT ;
    USE SIGNAL ;
    PORT
      LAYER M4 ;
        RECT  0 89.76 0.084 89.784 ;
    END
  END x[122]
  PIN x[123]
    DIRECTION INPUT ;
    USE SIGNAL ;
    PORT
      LAYER M4 ;
        RECT  0 89.808 0.084 89.832 ;
    END
  END x[123]
  PIN x[124]
    DIRECTION INPUT ;
    USE SIGNAL ;
    PORT
      LAYER M4 ;
        RECT  0 89.856 0.084 89.88 ;
    END
  END x[124]
  PIN x[125]
    DIRECTION INPUT ;
    USE SIGNAL ;
    PORT
      LAYER M4 ;
        RECT  0 89.904 0.084 89.928 ;
    END
  END x[125]
  PIN x[126]
    DIRECTION INPUT ;
    USE SIGNAL ;
    PORT
      LAYER M4 ;
        RECT  0 89.952 0.084 89.976 ;
    END
  END x[126]
  PIN x[127]
    DIRECTION INPUT ;
    USE SIGNAL ;
    PORT
      LAYER M4 ;
        RECT  0 90 0.084 90.024 ;
    END
  END x[127]
  PIN x[128]
    DIRECTION INPUT ;
    USE SIGNAL ;
    PORT
      LAYER M4 ;
        RECT  0 90.048 0.084 90.072 ;
    END
  END x[128]
  PIN x[129]
    DIRECTION INPUT ;
    USE SIGNAL ;
    PORT
      LAYER M4 ;
        RECT  0 90.096 0.084 90.12 ;
    END
  END x[129]
  PIN x[12]
    DIRECTION INPUT ;
    USE SIGNAL ;
    PORT
      LAYER M4 ;
        RECT  0 84.48 0.084 84.504 ;
    END
  END x[12]
  PIN x[130]
    DIRECTION INPUT ;
    USE SIGNAL ;
    PORT
      LAYER M4 ;
        RECT  0 90.144 0.084 90.168 ;
    END
  END x[130]
  PIN x[131]
    DIRECTION INPUT ;
    USE SIGNAL ;
    PORT
      LAYER M4 ;
        RECT  0 90.192 0.084 90.216 ;
    END
  END x[131]
  PIN x[132]
    DIRECTION INPUT ;
    USE SIGNAL ;
    PORT
      LAYER M4 ;
        RECT  0 90.24 0.084 90.264 ;
    END
  END x[132]
  PIN x[133]
    DIRECTION INPUT ;
    USE SIGNAL ;
    PORT
      LAYER M4 ;
        RECT  0 90.288 0.084 90.312 ;
    END
  END x[133]
  PIN x[134]
    DIRECTION INPUT ;
    USE SIGNAL ;
    PORT
      LAYER M4 ;
        RECT  0 90.336 0.084 90.36 ;
    END
  END x[134]
  PIN x[135]
    DIRECTION INPUT ;
    USE SIGNAL ;
    PORT
      LAYER M4 ;
        RECT  0 90.384 0.084 90.408 ;
    END
  END x[135]
  PIN x[136]
    DIRECTION INPUT ;
    USE SIGNAL ;
    PORT
      LAYER M4 ;
        RECT  0 90.432 0.084 90.456 ;
    END
  END x[136]
  PIN x[137]
    DIRECTION INPUT ;
    USE SIGNAL ;
    PORT
      LAYER M4 ;
        RECT  0 90.48 0.084 90.504 ;
    END
  END x[137]
  PIN x[138]
    DIRECTION INPUT ;
    USE SIGNAL ;
    PORT
      LAYER M4 ;
        RECT  0 90.528 0.084 90.552 ;
    END
  END x[138]
  PIN x[139]
    DIRECTION INPUT ;
    USE SIGNAL ;
    PORT
      LAYER M4 ;
        RECT  0 90.576 0.084 90.6 ;
    END
  END x[139]
  PIN x[13]
    DIRECTION INPUT ;
    USE SIGNAL ;
    PORT
      LAYER M4 ;
        RECT  0 84.528 0.084 84.552 ;
    END
  END x[13]
  PIN x[140]
    DIRECTION INPUT ;
    USE SIGNAL ;
    PORT
      LAYER M4 ;
        RECT  0 90.624 0.084 90.648 ;
    END
  END x[140]
  PIN x[141]
    DIRECTION INPUT ;
    USE SIGNAL ;
    PORT
      LAYER M4 ;
        RECT  0 90.672 0.084 90.696 ;
    END
  END x[141]
  PIN x[142]
    DIRECTION INPUT ;
    USE SIGNAL ;
    PORT
      LAYER M4 ;
        RECT  0 90.72 0.084 90.744 ;
    END
  END x[142]
  PIN x[143]
    DIRECTION INPUT ;
    USE SIGNAL ;
    PORT
      LAYER M4 ;
        RECT  0 90.768 0.084 90.792 ;
    END
  END x[143]
  PIN x[144]
    DIRECTION INPUT ;
    USE SIGNAL ;
    PORT
      LAYER M4 ;
        RECT  0 90.816 0.084 90.84 ;
    END
  END x[144]
  PIN x[145]
    DIRECTION INPUT ;
    USE SIGNAL ;
    PORT
      LAYER M4 ;
        RECT  0 90.864 0.084 90.888 ;
    END
  END x[145]
  PIN x[146]
    DIRECTION INPUT ;
    USE SIGNAL ;
    PORT
      LAYER M4 ;
        RECT  0 90.912 0.084 90.936 ;
    END
  END x[146]
  PIN x[147]
    DIRECTION INPUT ;
    USE SIGNAL ;
    PORT
      LAYER M4 ;
        RECT  0 90.96 0.084 90.984 ;
    END
  END x[147]
  PIN x[148]
    DIRECTION INPUT ;
    USE SIGNAL ;
    PORT
      LAYER M4 ;
        RECT  0 91.008 0.084 91.032 ;
    END
  END x[148]
  PIN x[149]
    DIRECTION INPUT ;
    USE SIGNAL ;
    PORT
      LAYER M4 ;
        RECT  0 91.056 0.084 91.08 ;
    END
  END x[149]
  PIN x[14]
    DIRECTION INPUT ;
    USE SIGNAL ;
    PORT
      LAYER M4 ;
        RECT  0 84.576 0.084 84.6 ;
    END
  END x[14]
  PIN x[150]
    DIRECTION INPUT ;
    USE SIGNAL ;
    PORT
      LAYER M4 ;
        RECT  0 91.104 0.084 91.128 ;
    END
  END x[150]
  PIN x[151]
    DIRECTION INPUT ;
    USE SIGNAL ;
    PORT
      LAYER M4 ;
        RECT  0 91.152 0.084 91.176 ;
    END
  END x[151]
  PIN x[152]
    DIRECTION INPUT ;
    USE SIGNAL ;
    PORT
      LAYER M4 ;
        RECT  0 91.2 0.084 91.224 ;
    END
  END x[152]
  PIN x[153]
    DIRECTION INPUT ;
    USE SIGNAL ;
    PORT
      LAYER M4 ;
        RECT  0 91.248 0.084 91.272 ;
    END
  END x[153]
  PIN x[154]
    DIRECTION INPUT ;
    USE SIGNAL ;
    PORT
      LAYER M4 ;
        RECT  0 91.296 0.084 91.32 ;
    END
  END x[154]
  PIN x[155]
    DIRECTION INPUT ;
    USE SIGNAL ;
    PORT
      LAYER M4 ;
        RECT  0 91.344 0.084 91.368 ;
    END
  END x[155]
  PIN x[156]
    DIRECTION INPUT ;
    USE SIGNAL ;
    PORT
      LAYER M4 ;
        RECT  0 91.392 0.084 91.416 ;
    END
  END x[156]
  PIN x[157]
    DIRECTION INPUT ;
    USE SIGNAL ;
    PORT
      LAYER M4 ;
        RECT  0 91.44 0.084 91.464 ;
    END
  END x[157]
  PIN x[158]
    DIRECTION INPUT ;
    USE SIGNAL ;
    PORT
      LAYER M4 ;
        RECT  0 91.488 0.084 91.512 ;
    END
  END x[158]
  PIN x[159]
    DIRECTION INPUT ;
    USE SIGNAL ;
    PORT
      LAYER M4 ;
        RECT  0 91.536 0.084 91.56 ;
    END
  END x[159]
  PIN x[15]
    DIRECTION INPUT ;
    USE SIGNAL ;
    PORT
      LAYER M4 ;
        RECT  0 84.624 0.084 84.648 ;
    END
  END x[15]
  PIN x[160]
    DIRECTION INPUT ;
    USE SIGNAL ;
    PORT
      LAYER M4 ;
        RECT  0 91.584 0.084 91.608 ;
    END
  END x[160]
  PIN x[161]
    DIRECTION INPUT ;
    USE SIGNAL ;
    PORT
      LAYER M4 ;
        RECT  0 91.632 0.084 91.656 ;
    END
  END x[161]
  PIN x[162]
    DIRECTION INPUT ;
    USE SIGNAL ;
    PORT
      LAYER M4 ;
        RECT  0 91.68 0.084 91.704 ;
    END
  END x[162]
  PIN x[163]
    DIRECTION INPUT ;
    USE SIGNAL ;
    PORT
      LAYER M4 ;
        RECT  0 91.728 0.084 91.752 ;
    END
  END x[163]
  PIN x[164]
    DIRECTION INPUT ;
    USE SIGNAL ;
    PORT
      LAYER M4 ;
        RECT  0 91.776 0.084 91.8 ;
    END
  END x[164]
  PIN x[165]
    DIRECTION INPUT ;
    USE SIGNAL ;
    PORT
      LAYER M4 ;
        RECT  0 91.824 0.084 91.848 ;
    END
  END x[165]
  PIN x[166]
    DIRECTION INPUT ;
    USE SIGNAL ;
    PORT
      LAYER M4 ;
        RECT  0 91.872 0.084 91.896 ;
    END
  END x[166]
  PIN x[167]
    DIRECTION INPUT ;
    USE SIGNAL ;
    PORT
      LAYER M4 ;
        RECT  0 91.92 0.084 91.944 ;
    END
  END x[167]
  PIN x[168]
    DIRECTION INPUT ;
    USE SIGNAL ;
    PORT
      LAYER M4 ;
        RECT  0 91.968 0.084 91.992 ;
    END
  END x[168]
  PIN x[169]
    DIRECTION INPUT ;
    USE SIGNAL ;
    PORT
      LAYER M4 ;
        RECT  0 92.016 0.084 92.04 ;
    END
  END x[169]
  PIN x[16]
    DIRECTION INPUT ;
    USE SIGNAL ;
    PORT
      LAYER M4 ;
        RECT  0 84.672 0.084 84.696 ;
    END
  END x[16]
  PIN x[170]
    DIRECTION INPUT ;
    USE SIGNAL ;
    PORT
      LAYER M4 ;
        RECT  0 92.064 0.084 92.088 ;
    END
  END x[170]
  PIN x[171]
    DIRECTION INPUT ;
    USE SIGNAL ;
    PORT
      LAYER M4 ;
        RECT  0 92.112 0.084 92.136 ;
    END
  END x[171]
  PIN x[172]
    DIRECTION INPUT ;
    USE SIGNAL ;
    PORT
      LAYER M4 ;
        RECT  0 92.16 0.084 92.184 ;
    END
  END x[172]
  PIN x[173]
    DIRECTION INPUT ;
    USE SIGNAL ;
    PORT
      LAYER M4 ;
        RECT  0 92.208 0.084 92.232 ;
    END
  END x[173]
  PIN x[174]
    DIRECTION INPUT ;
    USE SIGNAL ;
    PORT
      LAYER M4 ;
        RECT  0 92.256 0.084 92.28 ;
    END
  END x[174]
  PIN x[175]
    DIRECTION INPUT ;
    USE SIGNAL ;
    PORT
      LAYER M4 ;
        RECT  0 92.304 0.084 92.328 ;
    END
  END x[175]
  PIN x[176]
    DIRECTION INPUT ;
    USE SIGNAL ;
    PORT
      LAYER M4 ;
        RECT  0 92.352 0.084 92.376 ;
    END
  END x[176]
  PIN x[177]
    DIRECTION INPUT ;
    USE SIGNAL ;
    PORT
      LAYER M4 ;
        RECT  0 92.4 0.084 92.424 ;
    END
  END x[177]
  PIN x[178]
    DIRECTION INPUT ;
    USE SIGNAL ;
    PORT
      LAYER M4 ;
        RECT  0 92.448 0.084 92.472 ;
    END
  END x[178]
  PIN x[179]
    DIRECTION INPUT ;
    USE SIGNAL ;
    PORT
      LAYER M4 ;
        RECT  0 92.496 0.084 92.52 ;
    END
  END x[179]
  PIN x[17]
    DIRECTION INPUT ;
    USE SIGNAL ;
    PORT
      LAYER M4 ;
        RECT  0 84.72 0.084 84.744 ;
    END
  END x[17]
  PIN x[180]
    DIRECTION INPUT ;
    USE SIGNAL ;
    PORT
      LAYER M4 ;
        RECT  0 92.544 0.084 92.568 ;
    END
  END x[180]
  PIN x[181]
    DIRECTION INPUT ;
    USE SIGNAL ;
    PORT
      LAYER M4 ;
        RECT  0 92.592 0.084 92.616 ;
    END
  END x[181]
  PIN x[182]
    DIRECTION INPUT ;
    USE SIGNAL ;
    PORT
      LAYER M4 ;
        RECT  0 92.64 0.084 92.664 ;
    END
  END x[182]
  PIN x[183]
    DIRECTION INPUT ;
    USE SIGNAL ;
    PORT
      LAYER M4 ;
        RECT  0 92.688 0.084 92.712 ;
    END
  END x[183]
  PIN x[184]
    DIRECTION INPUT ;
    USE SIGNAL ;
    PORT
      LAYER M4 ;
        RECT  0 92.736 0.084 92.76 ;
    END
  END x[184]
  PIN x[185]
    DIRECTION INPUT ;
    USE SIGNAL ;
    PORT
      LAYER M4 ;
        RECT  0 92.784 0.084 92.808 ;
    END
  END x[185]
  PIN x[186]
    DIRECTION INPUT ;
    USE SIGNAL ;
    PORT
      LAYER M4 ;
        RECT  0 92.832 0.084 92.856 ;
    END
  END x[186]
  PIN x[187]
    DIRECTION INPUT ;
    USE SIGNAL ;
    PORT
      LAYER M4 ;
        RECT  0 92.88 0.084 92.904 ;
    END
  END x[187]
  PIN x[188]
    DIRECTION INPUT ;
    USE SIGNAL ;
    PORT
      LAYER M4 ;
        RECT  0 92.928 0.084 92.952 ;
    END
  END x[188]
  PIN x[189]
    DIRECTION INPUT ;
    USE SIGNAL ;
    PORT
      LAYER M4 ;
        RECT  0 92.976 0.084 93 ;
    END
  END x[189]
  PIN x[18]
    DIRECTION INPUT ;
    USE SIGNAL ;
    PORT
      LAYER M4 ;
        RECT  0 84.768 0.084 84.792 ;
    END
  END x[18]
  PIN x[190]
    DIRECTION INPUT ;
    USE SIGNAL ;
    PORT
      LAYER M4 ;
        RECT  0 93.024 0.084 93.048 ;
    END
  END x[190]
  PIN x[191]
    DIRECTION INPUT ;
    USE SIGNAL ;
    PORT
      LAYER M4 ;
        RECT  0 93.072 0.084 93.096 ;
    END
  END x[191]
  PIN x[192]
    DIRECTION INPUT ;
    USE SIGNAL ;
    PORT
      LAYER M4 ;
        RECT  0 93.12 0.084 93.144 ;
    END
  END x[192]
  PIN x[193]
    DIRECTION INPUT ;
    USE SIGNAL ;
    PORT
      LAYER M4 ;
        RECT  0 93.168 0.084 93.192 ;
    END
  END x[193]
  PIN x[194]
    DIRECTION INPUT ;
    USE SIGNAL ;
    PORT
      LAYER M4 ;
        RECT  0 93.216 0.084 93.24 ;
    END
  END x[194]
  PIN x[195]
    DIRECTION INPUT ;
    USE SIGNAL ;
    PORT
      LAYER M4 ;
        RECT  0 93.264 0.084 93.288 ;
    END
  END x[195]
  PIN x[196]
    DIRECTION INPUT ;
    USE SIGNAL ;
    PORT
      LAYER M4 ;
        RECT  0 93.312 0.084 93.336 ;
    END
  END x[196]
  PIN x[197]
    DIRECTION INPUT ;
    USE SIGNAL ;
    PORT
      LAYER M4 ;
        RECT  0 93.36 0.084 93.384 ;
    END
  END x[197]
  PIN x[198]
    DIRECTION INPUT ;
    USE SIGNAL ;
    PORT
      LAYER M4 ;
        RECT  0 93.408 0.084 93.432 ;
    END
  END x[198]
  PIN x[199]
    DIRECTION INPUT ;
    USE SIGNAL ;
    PORT
      LAYER M4 ;
        RECT  0 93.456 0.084 93.48 ;
    END
  END x[199]
  PIN x[19]
    DIRECTION INPUT ;
    USE SIGNAL ;
    PORT
      LAYER M4 ;
        RECT  0 84.816 0.084 84.84 ;
    END
  END x[19]
  PIN x[1]
    DIRECTION INPUT ;
    USE SIGNAL ;
    PORT
      LAYER M4 ;
        RECT  0 83.952 0.084 83.976 ;
    END
  END x[1]
  PIN x[200]
    DIRECTION INPUT ;
    USE SIGNAL ;
    PORT
      LAYER M4 ;
        RECT  0 93.504 0.084 93.528 ;
    END
  END x[200]
  PIN x[201]
    DIRECTION INPUT ;
    USE SIGNAL ;
    PORT
      LAYER M4 ;
        RECT  0 93.552 0.084 93.576 ;
    END
  END x[201]
  PIN x[202]
    DIRECTION INPUT ;
    USE SIGNAL ;
    PORT
      LAYER M4 ;
        RECT  0 93.6 0.084 93.624 ;
    END
  END x[202]
  PIN x[203]
    DIRECTION INPUT ;
    USE SIGNAL ;
    PORT
      LAYER M4 ;
        RECT  0 93.648 0.084 93.672 ;
    END
  END x[203]
  PIN x[204]
    DIRECTION INPUT ;
    USE SIGNAL ;
    PORT
      LAYER M4 ;
        RECT  0 93.696 0.084 93.72 ;
    END
  END x[204]
  PIN x[205]
    DIRECTION INPUT ;
    USE SIGNAL ;
    PORT
      LAYER M4 ;
        RECT  0 93.744 0.084 93.768 ;
    END
  END x[205]
  PIN x[206]
    DIRECTION INPUT ;
    USE SIGNAL ;
    PORT
      LAYER M4 ;
        RECT  0 93.792 0.084 93.816 ;
    END
  END x[206]
  PIN x[207]
    DIRECTION INPUT ;
    USE SIGNAL ;
    PORT
      LAYER M4 ;
        RECT  0 93.84 0.084 93.864 ;
    END
  END x[207]
  PIN x[208]
    DIRECTION INPUT ;
    USE SIGNAL ;
    PORT
      LAYER M4 ;
        RECT  0 93.888 0.084 93.912 ;
    END
  END x[208]
  PIN x[209]
    DIRECTION INPUT ;
    USE SIGNAL ;
    PORT
      LAYER M4 ;
        RECT  0 93.936 0.084 93.96 ;
    END
  END x[209]
  PIN x[20]
    DIRECTION INPUT ;
    USE SIGNAL ;
    PORT
      LAYER M4 ;
        RECT  0 84.864 0.084 84.888 ;
    END
  END x[20]
  PIN x[210]
    DIRECTION INPUT ;
    USE SIGNAL ;
    PORT
      LAYER M4 ;
        RECT  0 93.984 0.084 94.008 ;
    END
  END x[210]
  PIN x[211]
    DIRECTION INPUT ;
    USE SIGNAL ;
    PORT
      LAYER M4 ;
        RECT  0 94.032 0.084 94.056 ;
    END
  END x[211]
  PIN x[212]
    DIRECTION INPUT ;
    USE SIGNAL ;
    PORT
      LAYER M4 ;
        RECT  0 94.08 0.084 94.104 ;
    END
  END x[212]
  PIN x[213]
    DIRECTION INPUT ;
    USE SIGNAL ;
    PORT
      LAYER M4 ;
        RECT  0 94.128 0.084 94.152 ;
    END
  END x[213]
  PIN x[214]
    DIRECTION INPUT ;
    USE SIGNAL ;
    PORT
      LAYER M4 ;
        RECT  0 94.176 0.084 94.2 ;
    END
  END x[214]
  PIN x[215]
    DIRECTION INPUT ;
    USE SIGNAL ;
    PORT
      LAYER M4 ;
        RECT  0 94.224 0.084 94.248 ;
    END
  END x[215]
  PIN x[216]
    DIRECTION INPUT ;
    USE SIGNAL ;
    PORT
      LAYER M4 ;
        RECT  0 94.272 0.084 94.296 ;
    END
  END x[216]
  PIN x[217]
    DIRECTION INPUT ;
    USE SIGNAL ;
    PORT
      LAYER M4 ;
        RECT  0 94.32 0.084 94.344 ;
    END
  END x[217]
  PIN x[218]
    DIRECTION INPUT ;
    USE SIGNAL ;
    PORT
      LAYER M4 ;
        RECT  0 94.368 0.084 94.392 ;
    END
  END x[218]
  PIN x[219]
    DIRECTION INPUT ;
    USE SIGNAL ;
    PORT
      LAYER M4 ;
        RECT  0 94.416 0.084 94.44 ;
    END
  END x[219]
  PIN x[21]
    DIRECTION INPUT ;
    USE SIGNAL ;
    PORT
      LAYER M4 ;
        RECT  0 84.912 0.084 84.936 ;
    END
  END x[21]
  PIN x[220]
    DIRECTION INPUT ;
    USE SIGNAL ;
    PORT
      LAYER M4 ;
        RECT  0 94.464 0.084 94.488 ;
    END
  END x[220]
  PIN x[221]
    DIRECTION INPUT ;
    USE SIGNAL ;
    PORT
      LAYER M4 ;
        RECT  0 94.512 0.084 94.536 ;
    END
  END x[221]
  PIN x[222]
    DIRECTION INPUT ;
    USE SIGNAL ;
    PORT
      LAYER M4 ;
        RECT  0 94.56 0.084 94.584 ;
    END
  END x[222]
  PIN x[223]
    DIRECTION INPUT ;
    USE SIGNAL ;
    PORT
      LAYER M4 ;
        RECT  0 94.608 0.084 94.632 ;
    END
  END x[223]
  PIN x[224]
    DIRECTION INPUT ;
    USE SIGNAL ;
    PORT
      LAYER M4 ;
        RECT  0 94.656 0.084 94.68 ;
    END
  END x[224]
  PIN x[225]
    DIRECTION INPUT ;
    USE SIGNAL ;
    PORT
      LAYER M4 ;
        RECT  0 94.704 0.084 94.728 ;
    END
  END x[225]
  PIN x[226]
    DIRECTION INPUT ;
    USE SIGNAL ;
    PORT
      LAYER M4 ;
        RECT  0 94.752 0.084 94.776 ;
    END
  END x[226]
  PIN x[227]
    DIRECTION INPUT ;
    USE SIGNAL ;
    PORT
      LAYER M4 ;
        RECT  0 94.8 0.084 94.824 ;
    END
  END x[227]
  PIN x[228]
    DIRECTION INPUT ;
    USE SIGNAL ;
    PORT
      LAYER M4 ;
        RECT  0 94.848 0.084 94.872 ;
    END
  END x[228]
  PIN x[229]
    DIRECTION INPUT ;
    USE SIGNAL ;
    PORT
      LAYER M4 ;
        RECT  0 94.896 0.084 94.92 ;
    END
  END x[229]
  PIN x[22]
    DIRECTION INPUT ;
    USE SIGNAL ;
    PORT
      LAYER M4 ;
        RECT  0 84.96 0.084 84.984 ;
    END
  END x[22]
  PIN x[230]
    DIRECTION INPUT ;
    USE SIGNAL ;
    PORT
      LAYER M4 ;
        RECT  0 94.944 0.084 94.968 ;
    END
  END x[230]
  PIN x[231]
    DIRECTION INPUT ;
    USE SIGNAL ;
    PORT
      LAYER M4 ;
        RECT  0 94.992 0.084 95.016 ;
    END
  END x[231]
  PIN x[232]
    DIRECTION INPUT ;
    USE SIGNAL ;
    PORT
      LAYER M4 ;
        RECT  0 95.04 0.084 95.064 ;
    END
  END x[232]
  PIN x[233]
    DIRECTION INPUT ;
    USE SIGNAL ;
    PORT
      LAYER M4 ;
        RECT  0 95.088 0.084 95.112 ;
    END
  END x[233]
  PIN x[234]
    DIRECTION INPUT ;
    USE SIGNAL ;
    PORT
      LAYER M4 ;
        RECT  0 95.136 0.084 95.16 ;
    END
  END x[234]
  PIN x[235]
    DIRECTION INPUT ;
    USE SIGNAL ;
    PORT
      LAYER M4 ;
        RECT  0 95.184 0.084 95.208 ;
    END
  END x[235]
  PIN x[236]
    DIRECTION INPUT ;
    USE SIGNAL ;
    PORT
      LAYER M4 ;
        RECT  0 95.232 0.084 95.256 ;
    END
  END x[236]
  PIN x[237]
    DIRECTION INPUT ;
    USE SIGNAL ;
    PORT
      LAYER M4 ;
        RECT  0 95.28 0.084 95.304 ;
    END
  END x[237]
  PIN x[238]
    DIRECTION INPUT ;
    USE SIGNAL ;
    PORT
      LAYER M4 ;
        RECT  0 95.328 0.084 95.352 ;
    END
  END x[238]
  PIN x[239]
    DIRECTION INPUT ;
    USE SIGNAL ;
    PORT
      LAYER M4 ;
        RECT  0 95.376 0.084 95.4 ;
    END
  END x[239]
  PIN x[23]
    DIRECTION INPUT ;
    USE SIGNAL ;
    PORT
      LAYER M4 ;
        RECT  0 85.008 0.084 85.032 ;
    END
  END x[23]
  PIN x[240]
    DIRECTION INPUT ;
    USE SIGNAL ;
    PORT
      LAYER M4 ;
        RECT  0 95.424 0.084 95.448 ;
    END
  END x[240]
  PIN x[241]
    DIRECTION INPUT ;
    USE SIGNAL ;
    PORT
      LAYER M4 ;
        RECT  0 95.472 0.084 95.496 ;
    END
  END x[241]
  PIN x[242]
    DIRECTION INPUT ;
    USE SIGNAL ;
    PORT
      LAYER M4 ;
        RECT  0 95.52 0.084 95.544 ;
    END
  END x[242]
  PIN x[243]
    DIRECTION INPUT ;
    USE SIGNAL ;
    PORT
      LAYER M4 ;
        RECT  0 95.568 0.084 95.592 ;
    END
  END x[243]
  PIN x[244]
    DIRECTION INPUT ;
    USE SIGNAL ;
    PORT
      LAYER M4 ;
        RECT  0 95.616 0.084 95.64 ;
    END
  END x[244]
  PIN x[245]
    DIRECTION INPUT ;
    USE SIGNAL ;
    PORT
      LAYER M4 ;
        RECT  0 95.664 0.084 95.688 ;
    END
  END x[245]
  PIN x[246]
    DIRECTION INPUT ;
    USE SIGNAL ;
    PORT
      LAYER M4 ;
        RECT  0 95.712 0.084 95.736 ;
    END
  END x[246]
  PIN x[247]
    DIRECTION INPUT ;
    USE SIGNAL ;
    PORT
      LAYER M4 ;
        RECT  0 95.76 0.084 95.784 ;
    END
  END x[247]
  PIN x[248]
    DIRECTION INPUT ;
    USE SIGNAL ;
    PORT
      LAYER M4 ;
        RECT  0 95.808 0.084 95.832 ;
    END
  END x[248]
  PIN x[249]
    DIRECTION INPUT ;
    USE SIGNAL ;
    PORT
      LAYER M4 ;
        RECT  0 95.856 0.084 95.88 ;
    END
  END x[249]
  PIN x[24]
    DIRECTION INPUT ;
    USE SIGNAL ;
    PORT
      LAYER M4 ;
        RECT  0 85.056 0.084 85.08 ;
    END
  END x[24]
  PIN x[250]
    DIRECTION INPUT ;
    USE SIGNAL ;
    PORT
      LAYER M4 ;
        RECT  0 95.904 0.084 95.928 ;
    END
  END x[250]
  PIN x[251]
    DIRECTION INPUT ;
    USE SIGNAL ;
    PORT
      LAYER M4 ;
        RECT  0 95.952 0.084 95.976 ;
    END
  END x[251]
  PIN x[252]
    DIRECTION INPUT ;
    USE SIGNAL ;
    PORT
      LAYER M4 ;
        RECT  0 96 0.084 96.024 ;
    END
  END x[252]
  PIN x[253]
    DIRECTION INPUT ;
    USE SIGNAL ;
    PORT
      LAYER M4 ;
        RECT  0 96.048 0.084 96.072 ;
    END
  END x[253]
  PIN x[254]
    DIRECTION INPUT ;
    USE SIGNAL ;
    PORT
      LAYER M4 ;
        RECT  0 96.096 0.084 96.12 ;
    END
  END x[254]
  PIN x[255]
    DIRECTION INPUT ;
    USE SIGNAL ;
    PORT
      LAYER M4 ;
        RECT  0 96.144 0.084 96.168 ;
    END
  END x[255]
  PIN x[25]
    DIRECTION INPUT ;
    USE SIGNAL ;
    PORT
      LAYER M4 ;
        RECT  0 85.104 0.084 85.128 ;
    END
  END x[25]
  PIN x[26]
    DIRECTION INPUT ;
    USE SIGNAL ;
    PORT
      LAYER M4 ;
        RECT  0 85.152 0.084 85.176 ;
    END
  END x[26]
  PIN x[27]
    DIRECTION INPUT ;
    USE SIGNAL ;
    PORT
      LAYER M4 ;
        RECT  0 85.2 0.084 85.224 ;
    END
  END x[27]
  PIN x[28]
    DIRECTION INPUT ;
    USE SIGNAL ;
    PORT
      LAYER M4 ;
        RECT  0 85.248 0.084 85.272 ;
    END
  END x[28]
  PIN x[29]
    DIRECTION INPUT ;
    USE SIGNAL ;
    PORT
      LAYER M4 ;
        RECT  0 85.296 0.084 85.32 ;
    END
  END x[29]
  PIN x[2]
    DIRECTION INPUT ;
    USE SIGNAL ;
    PORT
      LAYER M4 ;
        RECT  0 84 0.084 84.024 ;
    END
  END x[2]
  PIN x[30]
    DIRECTION INPUT ;
    USE SIGNAL ;
    PORT
      LAYER M4 ;
        RECT  0 85.344 0.084 85.368 ;
    END
  END x[30]
  PIN x[31]
    DIRECTION INPUT ;
    USE SIGNAL ;
    PORT
      LAYER M4 ;
        RECT  0 85.392 0.084 85.416 ;
    END
  END x[31]
  PIN x[32]
    DIRECTION INPUT ;
    USE SIGNAL ;
    PORT
      LAYER M4 ;
        RECT  0 85.44 0.084 85.464 ;
    END
  END x[32]
  PIN x[33]
    DIRECTION INPUT ;
    USE SIGNAL ;
    PORT
      LAYER M4 ;
        RECT  0 85.488 0.084 85.512 ;
    END
  END x[33]
  PIN x[34]
    DIRECTION INPUT ;
    USE SIGNAL ;
    PORT
      LAYER M4 ;
        RECT  0 85.536 0.084 85.56 ;
    END
  END x[34]
  PIN x[35]
    DIRECTION INPUT ;
    USE SIGNAL ;
    PORT
      LAYER M4 ;
        RECT  0 85.584 0.084 85.608 ;
    END
  END x[35]
  PIN x[36]
    DIRECTION INPUT ;
    USE SIGNAL ;
    PORT
      LAYER M4 ;
        RECT  0 85.632 0.084 85.656 ;
    END
  END x[36]
  PIN x[37]
    DIRECTION INPUT ;
    USE SIGNAL ;
    PORT
      LAYER M4 ;
        RECT  0 85.68 0.084 85.704 ;
    END
  END x[37]
  PIN x[38]
    DIRECTION INPUT ;
    USE SIGNAL ;
    PORT
      LAYER M4 ;
        RECT  0 85.728 0.084 85.752 ;
    END
  END x[38]
  PIN x[39]
    DIRECTION INPUT ;
    USE SIGNAL ;
    PORT
      LAYER M4 ;
        RECT  0 85.776 0.084 85.8 ;
    END
  END x[39]
  PIN x[3]
    DIRECTION INPUT ;
    USE SIGNAL ;
    PORT
      LAYER M4 ;
        RECT  0 84.048 0.084 84.072 ;
    END
  END x[3]
  PIN x[40]
    DIRECTION INPUT ;
    USE SIGNAL ;
    PORT
      LAYER M4 ;
        RECT  0 85.824 0.084 85.848 ;
    END
  END x[40]
  PIN x[41]
    DIRECTION INPUT ;
    USE SIGNAL ;
    PORT
      LAYER M4 ;
        RECT  0 85.872 0.084 85.896 ;
    END
  END x[41]
  PIN x[42]
    DIRECTION INPUT ;
    USE SIGNAL ;
    PORT
      LAYER M4 ;
        RECT  0 85.92 0.084 85.944 ;
    END
  END x[42]
  PIN x[43]
    DIRECTION INPUT ;
    USE SIGNAL ;
    PORT
      LAYER M4 ;
        RECT  0 85.968 0.084 85.992 ;
    END
  END x[43]
  PIN x[44]
    DIRECTION INPUT ;
    USE SIGNAL ;
    PORT
      LAYER M4 ;
        RECT  0 86.016 0.084 86.04 ;
    END
  END x[44]
  PIN x[45]
    DIRECTION INPUT ;
    USE SIGNAL ;
    PORT
      LAYER M4 ;
        RECT  0 86.064 0.084 86.088 ;
    END
  END x[45]
  PIN x[46]
    DIRECTION INPUT ;
    USE SIGNAL ;
    PORT
      LAYER M4 ;
        RECT  0 86.112 0.084 86.136 ;
    END
  END x[46]
  PIN x[47]
    DIRECTION INPUT ;
    USE SIGNAL ;
    PORT
      LAYER M4 ;
        RECT  0 86.16 0.084 86.184 ;
    END
  END x[47]
  PIN x[48]
    DIRECTION INPUT ;
    USE SIGNAL ;
    PORT
      LAYER M4 ;
        RECT  0 86.208 0.084 86.232 ;
    END
  END x[48]
  PIN x[49]
    DIRECTION INPUT ;
    USE SIGNAL ;
    PORT
      LAYER M4 ;
        RECT  0 86.256 0.084 86.28 ;
    END
  END x[49]
  PIN x[4]
    DIRECTION INPUT ;
    USE SIGNAL ;
    PORT
      LAYER M4 ;
        RECT  0 84.096 0.084 84.12 ;
    END
  END x[4]
  PIN x[50]
    DIRECTION INPUT ;
    USE SIGNAL ;
    PORT
      LAYER M4 ;
        RECT  0 86.304 0.084 86.328 ;
    END
  END x[50]
  PIN x[51]
    DIRECTION INPUT ;
    USE SIGNAL ;
    PORT
      LAYER M4 ;
        RECT  0 86.352 0.084 86.376 ;
    END
  END x[51]
  PIN x[52]
    DIRECTION INPUT ;
    USE SIGNAL ;
    PORT
      LAYER M4 ;
        RECT  0 86.4 0.084 86.424 ;
    END
  END x[52]
  PIN x[53]
    DIRECTION INPUT ;
    USE SIGNAL ;
    PORT
      LAYER M4 ;
        RECT  0 86.448 0.084 86.472 ;
    END
  END x[53]
  PIN x[54]
    DIRECTION INPUT ;
    USE SIGNAL ;
    PORT
      LAYER M4 ;
        RECT  0 86.496 0.084 86.52 ;
    END
  END x[54]
  PIN x[55]
    DIRECTION INPUT ;
    USE SIGNAL ;
    PORT
      LAYER M4 ;
        RECT  0 86.544 0.084 86.568 ;
    END
  END x[55]
  PIN x[56]
    DIRECTION INPUT ;
    USE SIGNAL ;
    PORT
      LAYER M4 ;
        RECT  0 86.592 0.084 86.616 ;
    END
  END x[56]
  PIN x[57]
    DIRECTION INPUT ;
    USE SIGNAL ;
    PORT
      LAYER M4 ;
        RECT  0 86.64 0.084 86.664 ;
    END
  END x[57]
  PIN x[58]
    DIRECTION INPUT ;
    USE SIGNAL ;
    PORT
      LAYER M4 ;
        RECT  0 86.688 0.084 86.712 ;
    END
  END x[58]
  PIN x[59]
    DIRECTION INPUT ;
    USE SIGNAL ;
    PORT
      LAYER M4 ;
        RECT  0 86.736 0.084 86.76 ;
    END
  END x[59]
  PIN x[5]
    DIRECTION INPUT ;
    USE SIGNAL ;
    PORT
      LAYER M4 ;
        RECT  0 84.144 0.084 84.168 ;
    END
  END x[5]
  PIN x[60]
    DIRECTION INPUT ;
    USE SIGNAL ;
    PORT
      LAYER M4 ;
        RECT  0 86.784 0.084 86.808 ;
    END
  END x[60]
  PIN x[61]
    DIRECTION INPUT ;
    USE SIGNAL ;
    PORT
      LAYER M4 ;
        RECT  0 86.832 0.084 86.856 ;
    END
  END x[61]
  PIN x[62]
    DIRECTION INPUT ;
    USE SIGNAL ;
    PORT
      LAYER M4 ;
        RECT  0 86.88 0.084 86.904 ;
    END
  END x[62]
  PIN x[63]
    DIRECTION INPUT ;
    USE SIGNAL ;
    PORT
      LAYER M4 ;
        RECT  0 86.928 0.084 86.952 ;
    END
  END x[63]
  PIN x[64]
    DIRECTION INPUT ;
    USE SIGNAL ;
    PORT
      LAYER M4 ;
        RECT  0 86.976 0.084 87 ;
    END
  END x[64]
  PIN x[65]
    DIRECTION INPUT ;
    USE SIGNAL ;
    PORT
      LAYER M4 ;
        RECT  0 87.024 0.084 87.048 ;
    END
  END x[65]
  PIN x[66]
    DIRECTION INPUT ;
    USE SIGNAL ;
    PORT
      LAYER M4 ;
        RECT  0 87.072 0.084 87.096 ;
    END
  END x[66]
  PIN x[67]
    DIRECTION INPUT ;
    USE SIGNAL ;
    PORT
      LAYER M4 ;
        RECT  0 87.12 0.084 87.144 ;
    END
  END x[67]
  PIN x[68]
    DIRECTION INPUT ;
    USE SIGNAL ;
    PORT
      LAYER M4 ;
        RECT  0 87.168 0.084 87.192 ;
    END
  END x[68]
  PIN x[69]
    DIRECTION INPUT ;
    USE SIGNAL ;
    PORT
      LAYER M4 ;
        RECT  0 87.216 0.084 87.24 ;
    END
  END x[69]
  PIN x[6]
    DIRECTION INPUT ;
    USE SIGNAL ;
    PORT
      LAYER M4 ;
        RECT  0 84.192 0.084 84.216 ;
    END
  END x[6]
  PIN x[70]
    DIRECTION INPUT ;
    USE SIGNAL ;
    PORT
      LAYER M4 ;
        RECT  0 87.264 0.084 87.288 ;
    END
  END x[70]
  PIN x[71]
    DIRECTION INPUT ;
    USE SIGNAL ;
    PORT
      LAYER M4 ;
        RECT  0 87.312 0.084 87.336 ;
    END
  END x[71]
  PIN x[72]
    DIRECTION INPUT ;
    USE SIGNAL ;
    PORT
      LAYER M4 ;
        RECT  0 87.36 0.084 87.384 ;
    END
  END x[72]
  PIN x[73]
    DIRECTION INPUT ;
    USE SIGNAL ;
    PORT
      LAYER M4 ;
        RECT  0 87.408 0.084 87.432 ;
    END
  END x[73]
  PIN x[74]
    DIRECTION INPUT ;
    USE SIGNAL ;
    PORT
      LAYER M4 ;
        RECT  0 87.456 0.084 87.48 ;
    END
  END x[74]
  PIN x[75]
    DIRECTION INPUT ;
    USE SIGNAL ;
    PORT
      LAYER M4 ;
        RECT  0 87.504 0.084 87.528 ;
    END
  END x[75]
  PIN x[76]
    DIRECTION INPUT ;
    USE SIGNAL ;
    PORT
      LAYER M4 ;
        RECT  0 87.552 0.084 87.576 ;
    END
  END x[76]
  PIN x[77]
    DIRECTION INPUT ;
    USE SIGNAL ;
    PORT
      LAYER M4 ;
        RECT  0 87.6 0.084 87.624 ;
    END
  END x[77]
  PIN x[78]
    DIRECTION INPUT ;
    USE SIGNAL ;
    PORT
      LAYER M4 ;
        RECT  0 87.648 0.084 87.672 ;
    END
  END x[78]
  PIN x[79]
    DIRECTION INPUT ;
    USE SIGNAL ;
    PORT
      LAYER M4 ;
        RECT  0 87.696 0.084 87.72 ;
    END
  END x[79]
  PIN x[7]
    DIRECTION INPUT ;
    USE SIGNAL ;
    PORT
      LAYER M4 ;
        RECT  0 84.24 0.084 84.264 ;
    END
  END x[7]
  PIN x[80]
    DIRECTION INPUT ;
    USE SIGNAL ;
    PORT
      LAYER M4 ;
        RECT  0 87.744 0.084 87.768 ;
    END
  END x[80]
  PIN x[81]
    DIRECTION INPUT ;
    USE SIGNAL ;
    PORT
      LAYER M4 ;
        RECT  0 87.792 0.084 87.816 ;
    END
  END x[81]
  PIN x[82]
    DIRECTION INPUT ;
    USE SIGNAL ;
    PORT
      LAYER M4 ;
        RECT  0 87.84 0.084 87.864 ;
    END
  END x[82]
  PIN x[83]
    DIRECTION INPUT ;
    USE SIGNAL ;
    PORT
      LAYER M4 ;
        RECT  0 87.888 0.084 87.912 ;
    END
  END x[83]
  PIN x[84]
    DIRECTION INPUT ;
    USE SIGNAL ;
    PORT
      LAYER M4 ;
        RECT  0 87.936 0.084 87.96 ;
    END
  END x[84]
  PIN x[85]
    DIRECTION INPUT ;
    USE SIGNAL ;
    PORT
      LAYER M4 ;
        RECT  0 87.984 0.084 88.008 ;
    END
  END x[85]
  PIN x[86]
    DIRECTION INPUT ;
    USE SIGNAL ;
    PORT
      LAYER M4 ;
        RECT  0 88.032 0.084 88.056 ;
    END
  END x[86]
  PIN x[87]
    DIRECTION INPUT ;
    USE SIGNAL ;
    PORT
      LAYER M4 ;
        RECT  0 88.08 0.084 88.104 ;
    END
  END x[87]
  PIN x[88]
    DIRECTION INPUT ;
    USE SIGNAL ;
    PORT
      LAYER M4 ;
        RECT  0 88.128 0.084 88.152 ;
    END
  END x[88]
  PIN x[89]
    DIRECTION INPUT ;
    USE SIGNAL ;
    PORT
      LAYER M4 ;
        RECT  0 88.176 0.084 88.2 ;
    END
  END x[89]
  PIN x[8]
    DIRECTION INPUT ;
    USE SIGNAL ;
    PORT
      LAYER M4 ;
        RECT  0 84.288 0.084 84.312 ;
    END
  END x[8]
  PIN x[90]
    DIRECTION INPUT ;
    USE SIGNAL ;
    PORT
      LAYER M4 ;
        RECT  0 88.224 0.084 88.248 ;
    END
  END x[90]
  PIN x[91]
    DIRECTION INPUT ;
    USE SIGNAL ;
    PORT
      LAYER M4 ;
        RECT  0 88.272 0.084 88.296 ;
    END
  END x[91]
  PIN x[92]
    DIRECTION INPUT ;
    USE SIGNAL ;
    PORT
      LAYER M4 ;
        RECT  0 88.32 0.084 88.344 ;
    END
  END x[92]
  PIN x[93]
    DIRECTION INPUT ;
    USE SIGNAL ;
    PORT
      LAYER M4 ;
        RECT  0 88.368 0.084 88.392 ;
    END
  END x[93]
  PIN x[94]
    DIRECTION INPUT ;
    USE SIGNAL ;
    PORT
      LAYER M4 ;
        RECT  0 88.416 0.084 88.44 ;
    END
  END x[94]
  PIN x[95]
    DIRECTION INPUT ;
    USE SIGNAL ;
    PORT
      LAYER M4 ;
        RECT  0 88.464 0.084 88.488 ;
    END
  END x[95]
  PIN x[96]
    DIRECTION INPUT ;
    USE SIGNAL ;
    PORT
      LAYER M4 ;
        RECT  0 88.512 0.084 88.536 ;
    END
  END x[96]
  PIN x[97]
    DIRECTION INPUT ;
    USE SIGNAL ;
    PORT
      LAYER M4 ;
        RECT  0 88.56 0.084 88.584 ;
    END
  END x[97]
  PIN x[98]
    DIRECTION INPUT ;
    USE SIGNAL ;
    PORT
      LAYER M4 ;
        RECT  0 88.608 0.084 88.632 ;
    END
  END x[98]
  PIN x[99]
    DIRECTION INPUT ;
    USE SIGNAL ;
    PORT
      LAYER M4 ;
        RECT  0 88.656 0.084 88.68 ;
    END
  END x[99]
  PIN x[9]
    DIRECTION INPUT ;
    USE SIGNAL ;
    PORT
      LAYER M4 ;
        RECT  0 84.336 0.084 84.36 ;
    END
  END x[9]
  PIN y[0]
    DIRECTION OUTPUT ;
    USE SIGNAL ;
    PORT
      LAYER M4 ;
        RECT  179.916 114.384 180 114.408 ;
    END
  END y[0]
  PIN y[10]
    DIRECTION OUTPUT ;
    USE SIGNAL ;
    PORT
      LAYER M4 ;
        RECT  179.916 114.864 180 114.888 ;
    END
  END y[10]
  PIN y[11]
    DIRECTION OUTPUT ;
    USE SIGNAL ;
    PORT
      LAYER M4 ;
        RECT  179.916 114.912 180 114.936 ;
    END
  END y[11]
  PIN y[12]
    DIRECTION OUTPUT ;
    USE SIGNAL ;
    PORT
      LAYER M4 ;
        RECT  179.916 114.96 180 114.984 ;
    END
  END y[12]
  PIN y[13]
    DIRECTION OUTPUT ;
    USE SIGNAL ;
    PORT
      LAYER M4 ;
        RECT  179.916 115.008 180 115.032 ;
    END
  END y[13]
  PIN y[14]
    DIRECTION OUTPUT ;
    USE SIGNAL ;
    PORT
      LAYER M4 ;
        RECT  179.916 115.056 180 115.08 ;
    END
  END y[14]
  PIN y[15]
    DIRECTION OUTPUT ;
    USE SIGNAL ;
    PORT
      LAYER M4 ;
        RECT  179.916 115.104 180 115.128 ;
    END
  END y[15]
  PIN y[16]
    DIRECTION OUTPUT ;
    USE SIGNAL ;
    PORT
      LAYER M4 ;
        RECT  179.916 115.152 180 115.176 ;
    END
  END y[16]
  PIN y[17]
    DIRECTION OUTPUT ;
    USE SIGNAL ;
    PORT
      LAYER M4 ;
        RECT  179.916 115.2 180 115.224 ;
    END
  END y[17]
  PIN y[18]
    DIRECTION OUTPUT ;
    USE SIGNAL ;
    PORT
      LAYER M4 ;
        RECT  179.916 115.248 180 115.272 ;
    END
  END y[18]
  PIN y[19]
    DIRECTION OUTPUT ;
    USE SIGNAL ;
    PORT
      LAYER M4 ;
        RECT  179.916 115.296 180 115.32 ;
    END
  END y[19]
  PIN y[1]
    DIRECTION OUTPUT ;
    USE SIGNAL ;
    PORT
      LAYER M4 ;
        RECT  179.916 114.432 180 114.456 ;
    END
  END y[1]
  PIN y[20]
    DIRECTION OUTPUT ;
    USE SIGNAL ;
    PORT
      LAYER M4 ;
        RECT  179.916 115.344 180 115.368 ;
    END
  END y[20]
  PIN y[21]
    DIRECTION OUTPUT ;
    USE SIGNAL ;
    PORT
      LAYER M4 ;
        RECT  179.916 115.392 180 115.416 ;
    END
  END y[21]
  PIN y[22]
    DIRECTION OUTPUT ;
    USE SIGNAL ;
    PORT
      LAYER M4 ;
        RECT  179.916 115.44 180 115.464 ;
    END
  END y[22]
  PIN y[23]
    DIRECTION OUTPUT ;
    USE SIGNAL ;
    PORT
      LAYER M4 ;
        RECT  179.916 115.488 180 115.512 ;
    END
  END y[23]
  PIN y[24]
    DIRECTION OUTPUT ;
    USE SIGNAL ;
    PORT
      LAYER M4 ;
        RECT  179.916 115.536 180 115.56 ;
    END
  END y[24]
  PIN y[25]
    DIRECTION OUTPUT ;
    USE SIGNAL ;
    PORT
      LAYER M4 ;
        RECT  179.916 115.584 180 115.608 ;
    END
  END y[25]
  PIN y[26]
    DIRECTION OUTPUT ;
    USE SIGNAL ;
    PORT
      LAYER M4 ;
        RECT  179.916 115.632 180 115.656 ;
    END
  END y[26]
  PIN y[27]
    DIRECTION OUTPUT ;
    USE SIGNAL ;
    PORT
      LAYER M4 ;
        RECT  179.916 115.68 180 115.704 ;
    END
  END y[27]
  PIN y[28]
    DIRECTION OUTPUT ;
    USE SIGNAL ;
    PORT
      LAYER M4 ;
        RECT  179.916 115.728 180 115.752 ;
    END
  END y[28]
  PIN y[29]
    DIRECTION OUTPUT ;
    USE SIGNAL ;
    PORT
      LAYER M4 ;
        RECT  179.916 115.776 180 115.8 ;
    END
  END y[29]
  PIN y[2]
    DIRECTION OUTPUT ;
    USE SIGNAL ;
    PORT
      LAYER M4 ;
        RECT  179.916 114.48 180 114.504 ;
    END
  END y[2]
  PIN y[30]
    DIRECTION OUTPUT ;
    USE SIGNAL ;
    PORT
      LAYER M4 ;
        RECT  179.916 115.824 180 115.848 ;
    END
  END y[30]
  PIN y[31]
    DIRECTION OUTPUT ;
    USE SIGNAL ;
    PORT
      LAYER M4 ;
        RECT  179.916 115.872 180 115.896 ;
    END
  END y[31]
  PIN y[3]
    DIRECTION OUTPUT ;
    USE SIGNAL ;
    PORT
      LAYER M4 ;
        RECT  179.916 114.528 180 114.552 ;
    END
  END y[3]
  PIN y[4]
    DIRECTION OUTPUT ;
    USE SIGNAL ;
    PORT
      LAYER M4 ;
        RECT  179.916 114.576 180 114.6 ;
    END
  END y[4]
  PIN y[5]
    DIRECTION OUTPUT ;
    USE SIGNAL ;
    PORT
      LAYER M4 ;
        RECT  179.916 114.624 180 114.648 ;
    END
  END y[5]
  PIN y[6]
    DIRECTION OUTPUT ;
    USE SIGNAL ;
    PORT
      LAYER M4 ;
        RECT  179.916 114.672 180 114.696 ;
    END
  END y[6]
  PIN y[7]
    DIRECTION OUTPUT ;
    USE SIGNAL ;
    PORT
      LAYER M4 ;
        RECT  179.916 114.72 180 114.744 ;
    END
  END y[7]
  PIN y[8]
    DIRECTION OUTPUT ;
    USE SIGNAL ;
    PORT
      LAYER M4 ;
        RECT  179.916 114.768 180 114.792 ;
    END
  END y[8]
  PIN y[9]
    DIRECTION OUTPUT ;
    USE SIGNAL ;
    PORT
      LAYER M4 ;
        RECT  179.916 114.816 180 114.84 ;
    END
  END y[9]
  PIN VDD
    DIRECTION INOUT ;
    USE POWER ;
    PORT
      LAYER M6 ;
        RECT  1.44 177.2 178.596 177.488 ;
        RECT  1.44 166.4 178.596 166.688 ;
        RECT  1.44 155.6 178.596 155.888 ;
        RECT  1.44 144.8 178.596 145.088 ;
        RECT  1.44 134 178.596 134.288 ;
        RECT  1.44 123.2 178.596 123.488 ;
        RECT  1.44 112.4 178.596 112.688 ;
        RECT  1.44 101.6 178.596 101.888 ;
        RECT  1.44 90.8 178.596 91.088 ;
        RECT  1.44 80 178.596 80.288 ;
        RECT  1.44 69.2 178.596 69.488 ;
        RECT  1.44 58.4 178.596 58.688 ;
        RECT  1.44 47.6 178.596 47.888 ;
        RECT  1.44 36.8 178.596 37.088 ;
        RECT  1.44 26 178.596 26.288 ;
        RECT  1.44 15.2 178.596 15.488 ;
        RECT  1.44 4.4 178.596 4.688 ;
        RECT  1.44 178.614 178.596 178.902 ;
        RECT  1.44 1.188 178.596 1.476 ;
    END
  END VDD
  PIN VSS
    DIRECTION INOUT ;
    USE GROUND ;
    PORT
      LAYER M6 ;
        RECT  1.44 176.816 178.596 177.104 ;
        RECT  1.44 166.016 178.596 166.304 ;
        RECT  1.44 155.216 178.596 155.504 ;
        RECT  1.44 144.416 178.596 144.704 ;
        RECT  1.44 133.616 178.596 133.904 ;
        RECT  1.44 122.816 178.596 123.104 ;
        RECT  1.44 112.016 178.596 112.304 ;
        RECT  1.44 101.216 178.596 101.504 ;
        RECT  1.44 90.416 178.596 90.704 ;
        RECT  1.44 79.616 178.596 79.904 ;
        RECT  1.44 68.816 178.596 69.104 ;
        RECT  1.44 58.016 178.596 58.304 ;
        RECT  1.44 47.216 178.596 47.504 ;
        RECT  1.44 36.416 178.596 36.704 ;
        RECT  1.44 25.616 178.596 25.904 ;
        RECT  1.44 14.816 178.596 15.104 ;
        RECT  1.44 4.016 178.596 4.304 ;
        RECT  1.632 178.23 178.404 178.518 ;
        RECT  1.632 1.572 178.404 1.86 ;
    END
  END VSS
  OBS
    LAYER RVTN ;
     RECT  0 0 180 180 ;
    LAYER RVTP ;
     RECT  0 0 180 180 ;
    LAYER M1 ;
     RECT  0 0 180 180 ;
    LAYER M2 ;
     RECT  0 0 180 180 ;
    LAYER M3 ;
     RECT  0 0 180 180 ;
    LAYER M4 ;
     RECT  0 0 180 180 ;
    LAYER M5 ;
     RECT  0 0 180 180 ;
    LAYER M6 ;
     RECT  0 0 180 180 ;
  END
END ot_gpu_tc16
END LIBRARY
